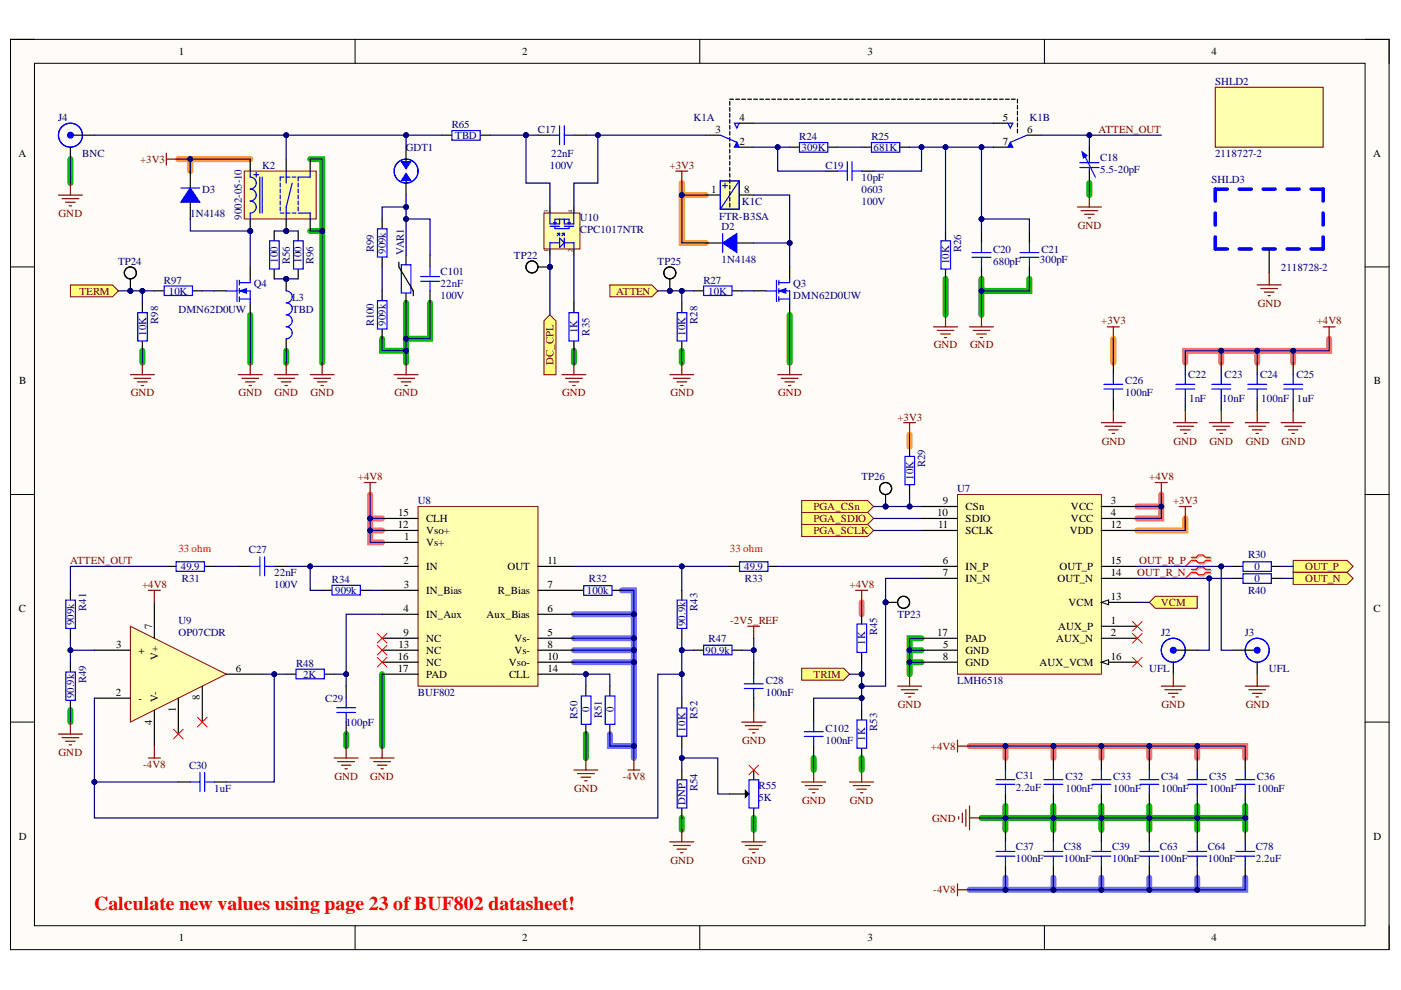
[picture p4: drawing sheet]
<svg xmlns="http://www.w3.org/2000/svg" width="297mm" height="210mm" viewBox="0 0 297 210" stroke-linecap="round" stroke-linejoin="round" font-family="sans-serif">
<defs><g id="words">
<text font-size="4.1" fill="#f00" x="20" y="192.9">Calculate new values using page 23 ofBUF802 datasheet!</text>
<g font-size="2.3">
<text x="37.9" y="11.7">1</text>
<text x="110.7" y="11.7">2</text>
<text x="183.9" y="11.7">3</text>
<text x="256.8" y="11.7">4</text>
<text x="151.7" y="28.1">3</text>
<text x="156.8" y="25.6">4</text>
<text x="212.6" y="25.6">5</text>
<text x="217.8" y="28.1">6</text>
<text x="3.9" y="33.3">A</text>
<text x="156.8" y="30.8">2</text>
<text x="212.6" y="30.8">7</text>
<text x="291.1" y="33.3">A</text>
<text x="150.8" y="40.9">1</text>
<text x="157.8" y="40.9">8</text>
<text x="4.1" y="81.5">B</text>
<text x="291.3" y="81.5">B</text>
<text x="199.9" y="106.9">9</text>
<text x="235.5" y="106.9">3</text>
<text x="84.3" y="112">12</text>
<text x="84.4" y="109.5">15</text>
<text x="90.4" y="113.3">Vso+</text>
<text x="90.4" y="110.7">CLH</text>
<text x="198.7" y="109.5">10</text>
<text x="198.9" y="112">11</text>
<text x="204.7" y="108.2">CSn</text>
<text x="204.7" y="110.7">SDIO</text>
<text x="204.7" y="113.3">SCLK</text>
<text x="226.8" y="113.3">VDD</text>
<text x="227.1" y="108.2">VCC</text>
<text x="227.1" y="110.7">VCC</text>
<text x="235.5" y="112">12</text>
<text x="235.5" y="109.5">4</text>
<text x="85.5" y="119.6">2</text>
<text x="85.7" y="114.5">1</text>
<text x="90.4" y="115.8">Vs+</text>
<text x="116.1" y="119.6">11</text>
<text x="199.9" y="119.6">6</text>
<text x="235.5" y="119.6">15</text>
<text x="85.6" y="124.7">3</text>
<text x="90.4" y="120.9">IN</text>
<text x="90.4" y="125.9">IN_Bias</text>
<text x="105.6" y="125.9">R_Bias</text>
<text x="107.6" y="120.9">OUT</text>
<text x="116.1" y="124.7">7</text>
<text x="199.9" y="122.1">7</text>
<text x="204.7" y="120.9">IN_P</text>
<text x="204.7" y="123.4">IN_N</text>
<text x="224.2" y="123.4">OUT_N</text>
<text x="224.6" y="120.9">OUT_P</text>
<text x="235.5" y="122.1">14</text>
<text x="4" y="129.7">C</text>
<text x="85.5" y="129.7">4</text>
<text x="90.4" y="131">IN_Aux</text>
<text x="103.1" y="131">Aux_Bias</text>
<text x="116.1" y="129.7">6</text>
<text x="226.6" y="128.5">VCM</text>
<text x="235.5" y="127.2">13</text>
<text x="291.2" y="129.7">C</text>
<text x="24.6" y="137.4">3</text>
<text x="32.2" y="133.3" transform="rotate(-90 32.2 133.3)">7</text>
<text x="84.5" y="137.4">13</text>
<text x="85.5" y="134.8">9</text>
<text x="90.4" y="136.1">NC</text>
<text x="109" y="136.1">Vs-</text>
<text x="116.1" y="134.8">5</text>
<text x="116.1" y="137.4">8</text>
<text x="198.7" y="134.8">17</text>
<text x="200" y="137.4">5</text>
<text x="204.7" y="136.1">PAD</text>
<text x="223.9" y="136.1">AUX_N</text>
<text x="224.4" y="133.6">AUX_P</text>
<text x="235.5" y="132.3">1</text>
<text x="235.5" y="134.8">2</text>
<text x="29.4" y="138.6">+</text>
<text x="33.5" y="140" transform="rotate(-90 33.5 140)">V+</text>
<text x="50" y="142.4">6</text>
<text x="84.3" y="139.9">16</text>
<text x="84.3" y="142.4">17</text>
<text x="90.4" y="138.6">NC</text>
<text x="90.4" y="141.2">NC</text>
<text x="90.4" y="143.7">PAD</text>
<text x="107.9" y="141.2">Vso-</text>
<text x="107.9" y="143.7">CLL</text>
<text x="109" y="138.6">Vs-</text>
<text x="116.1" y="139.9">10</text>
<text x="116.1" y="142.4">14</text>
<text x="199.9" y="139.9">8</text>
<text x="204.7" y="141.2">GND</text>
<text x="204.7" y="138.6">GND</text>
<text x="220.4" y="141.2">AUX_VCM</text>
<text x="235.5" y="139.9">16</text>
<text x="24.5" y="147.5">2</text>
<text x="29.4" y="148.9">-</text>
<text x="33.5" y="148.8" transform="rotate(-90 33.5 148.8)">V-</text>
<text x="42.4" y="148.5" transform="rotate(-90 42.4 148.5)">8</text>
<text x="32.2" y="153.7" transform="rotate(-90 32.2 153.7)">4</text>
<text x="37.3" y="150.9" transform="rotate(-90 37.3 150.9)">1</text>
<text x="4" y="178">D</text>
<text x="291.2" y="178">D</text>
<text x="37.9" y="199.6">1</text>
<text x="110.7" y="199.6">2</text>
<text x="183.9" y="199.6">3</text>
<text x="256.8" y="199.6">4</text>
</g>
<g font-size="2.3" fill="#000080">
<text x="257.6" y="18">SHLD2</text>
<text x="12.4" y="25.6">J4</text>
<text x="95.8" y="27.2">R65</text>
<text x="96.5" y="29.5">TBD</text>
<text x="114" y="28.1">C17</text>
<text x="147" y="25.6">K1A</text>
<text x="169.5" y="29.7">R24</text>
<text x="184.8" y="29.7">R25</text>
<text x="218.3" y="25.6">K1B</text>
<text x="17.4" y="33.3">BNC</text>
<text x="55.6" y="35.8">K2</text>
<text x="86" y="32">GDT1</text>
<text x="116.6" y="35.8">100V</text>
<text x="116.8" y="33.3">22nF</text>
<text x="170" y="32">309K</text>
<text x="175" y="35.8">C19</text>
<text x="185.2" y="32">681K</text>
<text x="233.2" y="34.1">C18</text>
<text x="257.6" y="33.3">2118727-2</text>
<text x="42.9" y="40.9">D3</text>
<text x="182.7" y="40.9">0603</text>
<text x="182.7" y="38.4">10pF</text>
<text x="233.2" y="36.6">5.5-20pF</text>
<text x="256.8" y="38.9">SHLD3</text>
<text x="40.4" y="46">1N4148</text>
<text x="51.3" y="46.7" transform="rotate(-90 51.3 46.7)">9002-05-10</text>
<text x="122.9" y="46.8">U10</text>
<text x="152.4" y="46.7">FTR-B3SA</text>
<text x="157.3" y="43.4">K1C</text>
<text x="182.7" y="43.4">100V</text>
<text x="79.3" y="53.4" transform="rotate(-90 79.3 53.4)">R99</text>
<text x="81.8" y="53.8" transform="rotate(-90 81.8 53.8)">909k</text>
<text x="122.9" y="49.4">CPC1017NTR</text>
<text x="153" y="48.8">D2</text>
<text x="203.8" y="53.4" transform="rotate(-90 203.8 53.4)">R26</text>
<text x="210.6" y="53.6">C20</text>
<text x="220.8" y="53.6">C21</text>
<text x="25" y="56.1">TP24</text>
<text x="58.9" y="55.7" transform="rotate(-90 58.9 55.7)">100</text>
<text x="61.4" y="56" transform="rotate(-90 61.4 56)">R56</text>
<text x="64" y="55.7" transform="rotate(-90 64 55.7)">100</text>
<text x="66.5" y="56" transform="rotate(-90 66.5 56)">R96</text>
<text x="85.6" y="54.1" transform="rotate(-90 85.6 54.1)">VAR1</text>
<text x="93.4" y="58.4">C101</text>
<text x="109" y="54.9">TP22</text>
<text x="139.4" y="56.1">TP25</text>
<text x="153" y="55.9">1N4148</text>
<text x="201.3" y="56" transform="rotate(-90 201.3 56)">10K</text>
<text x="210.6" y="56.1">680pF</text>
<text x="220.5" y="55.9">300pF</text>
<text x="271.6" y="57.4">2118728-2</text>
<text x="34.8" y="60.2">R97</text>
<text x="35.8" y="62.5">10K</text>
<text x="53.8" y="60.9">Q4</text>
<text x="61.9" y="63.7">L3</text>
<text x="93.4" y="63.5">100V</text>
<text x="93.4" y="60.9">22nF</text>
<text x="149.1" y="60.2">R27</text>
<text x="150.2" y="62.5">10K</text>
<text x="168.2" y="60.9">Q3</text>
<text x="168.2" y="63.5">DMN62D0UW</text>
<text x="31" y="71.3" transform="rotate(-90 31 71.3)">10K</text>
<text x="33.5" y="68.6" transform="rotate(-90 33.5 68.6)">R98</text>
<text x="37.8" y="66.3">DMN62D0UW</text>
<text x="61.9" y="66.3">TBD</text>
<text x="79.3" y="69.2" transform="rotate(-90 79.3 69.2)">R100</text>
<text x="81.8" y="69.1" transform="rotate(-90 81.8 69.1)">909k</text>
<text x="122.4" y="70.7" transform="rotate(-90 122.4 70.7)">1K</text>
<text x="125" y="71.2" transform="rotate(-90 125 71.2)">R35</text>
<text x="145.3" y="71.3" transform="rotate(-90 145.3 71.3)">10K</text>
<text x="147.9" y="68.6" transform="rotate(-90 147.9 68.6)">R28</text>
<text x="238.6" y="81.5">C26</text>
<text x="251.9" y="80.2">C22</text>
<text x="259.6" y="80.2">C23</text>
<text x="267.2" y="80.2">C24</text>
<text x="274.9" y="80.2">C25</text>
<text x="238.6" y="84">100nF</text>
<text x="252.1" y="85.3">1nF</text>
<text x="259.1" y="85.3">10nF</text>
<text x="267.4" y="85.3">100nF</text>
<text x="274.9" y="85.3">1uF</text>
<text x="182.7" y="101.9">TP26</text>
<text x="193.6" y="101.8" transform="rotate(-90 193.6 101.8)">10K</text>
<text x="196.2" y="99.1" transform="rotate(-90 196.2 99.1)">R29</text>
<text x="88.6" y="106.9">U8</text>
<text x="203" y="104.4">U7</text>
<text x="52.8" y="117.3">C27</text>
<text x="264.6" y="118.3">R30</text>
<text x="38.3" y="120.9">49.9</text>
<text x="38.6" y="123.4">R31</text>
<text x="58.1" y="124.7">100V</text>
<text x="58.1" y="122.1">22nF</text>
<text x="70.4" y="123.7">R34</text>
<text x="71.1" y="125.9">909k</text>
<text x="124.4" y="125.9">100k</text>
<text x="124.9" y="123.4">R32</text>
<text x="157.8" y="120.9">49.9</text>
<text x="157.9" y="123.4">R33</text>
<text x="264.6" y="125.9">R40</text>
<text x="266" y="120.9">0</text>
<text x="266" y="123.4">0</text>
<text x="18.3" y="129.5" transform="rotate(-90 18.3 129.5)">R41</text>
<text x="147.9" y="129.5" transform="rotate(-90 147.9 129.5)">R43</text>
<text x="190.3" y="131">TP23</text>
<text x="15.7" y="132.5" transform="rotate(-90 15.7 132.5)">909k</text>
<text x="37.8" y="132.3">U9</text>
<text x="37.8" y="134.8">OP07CDR</text>
<text x="145.3" y="132.8" transform="rotate(-90 145.3 132.8)">90.9k</text>
<text x="150.2" y="136.1">R47</text>
<text x="183.4" y="136.8" transform="rotate(-90 183.4 136.8)">1K</text>
<text x="186" y="134.7" transform="rotate(-90 186 134.7)">R45</text>
<text x="246.2" y="134.8">J2</text>
<text x="264" y="134.8">J3</text>
<text x="62.8" y="141.4">R48</text>
<text x="64.3" y="143.7">2K</text>
<text x="149.6" y="138.6">90.9k</text>
<text x="243.6" y="142.4">UFL</text>
<text x="269" y="142.4">UFL</text>
<text x="15.7" y="148.1" transform="rotate(-90 15.7 148.1)">90.9k</text>
<text x="18.3" y="144.8" transform="rotate(-90 18.3 144.8)">R49</text>
<text x="68.9" y="148.9">C29</text>
<text x="88.6" y="147.5">BUF802</text>
<text x="162.3" y="145">C28</text>
<text x="162.3" y="147.5">100nF</text>
<text x="203" y="145">LMH6518</text>
<text x="73.3" y="153.9">100pF</text>
<text x="122.4" y="152.4" transform="rotate(-90 122.4 152.4)">R50</text>
<text x="125" y="151.1" transform="rotate(-90 125 151.1)">0</text>
<text x="127.6" y="152.3" transform="rotate(-90 127.6 152.3)">R51</text>
<text x="130.1" y="151.1" transform="rotate(-90 130.1 151.1)">0</text>
<text x="145.3" y="155.1" transform="rotate(-90 145.3 155.1)">10K</text>
<text x="147.9" y="152.4" transform="rotate(-90 147.9 152.4)">R52</text>
<text x="175" y="155.2">C102</text>
<text x="186" y="154.9" transform="rotate(-90 186 154.9)">R53</text>
<text x="175" y="157.7">100nF</text>
<text x="183.4" y="157.1" transform="rotate(-90 183.4 157.1)">1K</text>
<text x="40.1" y="163.1">C30</text>
<text x="45.4" y="167.9">1uF</text>
<text x="147.9" y="167.7" transform="rotate(-90 147.9 167.7)">R54</text>
<text x="160.8" y="167.4">R55</text>
<text x="215.4" y="165.1">C31</text>
<text x="215.4" y="167.6">2.2uF</text>
<text x="225.9" y="165.3">C32</text>
<text x="225.9" y="167.9">100nF</text>
<text x="236" y="165.3">C33</text>
<text x="236" y="167.9">100nF</text>
<text x="246.2" y="165.3">C34</text>
<text x="246.2" y="167.9">100nF</text>
<text x="256.3" y="165.3">C35</text>
<text x="256.3" y="167.9">100nF</text>
<text x="266.5" y="165.3">C36</text>
<text x="266.5" y="167.9">100nF</text>
<text x="145.3" y="170.6" transform="rotate(-90 145.3 170.6)">DNP</text>
<text x="160.8" y="169.9">5K</text>
<text x="215.4" y="180.3">C37</text>
<text x="215.4" y="182.8">100nF</text>
<text x="225.5" y="180.3">C38</text>
<text x="225.5" y="182.8">100nF</text>
<text x="235.8" y="180.3">C39</text>
<text x="235.8" y="182.8">100nF</text>
<text x="245.9" y="180.3">C63</text>
<text x="245.9" y="182.8">100nF</text>
<text x="256.1" y="180.3">C64</text>
<text x="256.1" y="182.8">100nF</text>
<text x="266.2" y="180.3">C78</text>
<text x="266.2" y="182.8">2.2uF</text>
</g>
<g font-size="2.3" fill="#800000">
<text x="232.9" y="28.1">ATTEN_OUT</text>
<text x="29.7" y="34.6">+3V3</text>
<text x="142" y="35.8">+3V3</text>
<text x="12.4" y="46">GND</text>
<text x="228.5" y="48.5">GND</text>
<text x="16.8" y="62.5">TERM</text>
<text x="130.6" y="62.5">ATTEN</text>
<text x="266.7" y="65">GND</text>
<text x="233.5" y="68.8">+3V3</text>
<text x="279.2" y="68.8">+4V8</text>
<text x="117.3" y="77.3" transform="rotate(-90 117.3 77.3)">DC_CPL</text>
<text x="198" y="73.9">GND</text>
<text x="205.7" y="73.9">GND</text>
<text x="27.7" y="84">GND</text>
<text x="50.6" y="84">GND</text>
<text x="58.2" y="84">GND</text>
<text x="65.8" y="84">GND</text>
<text x="83.7" y="84">GND</text>
<text x="119.2" y="84">GND</text>
<text x="142.1" y="84">GND</text>
<text x="165" y="84">GND</text>
<text x="190.3" y="89.2">+3V3</text>
<text x="233.6" y="94.2">GND</text>
<text x="248.8" y="94.2">GND</text>
<text x="256.4" y="94.2">GND</text>
<text x="264.1" y="94.2">GND</text>
<text x="271.7" y="94.2">GND</text>
<text x="75.9" y="101.9">+4V8</text>
<text x="243.6" y="101.9">+4V8</text>
<text x="248.7" y="106.9">+3V3</text>
<text x="172.5" y="108.2">PGA_CSn</text>
<text x="172.5" y="113.3">PGA_SCLK</text>
<text x="172.5" y="110.7">PGA_SDIO</text>
<text x="14.9" y="119.6">ATTEN_OUT</text>
<text x="241.5" y="119.6">OUT_R_P</text>
<text x="30.1" y="124.7">+4V8</text>
<text x="180.1" y="124.7">+4V8</text>
<text x="241.1" y="122.1">OUT_R_N</text>
<text x="276.7" y="120.9">OUT_P</text>
<text x="276.7" y="123.4">OUT_N</text>
<text x="246.1" y="128.5">VCM</text>
<text x="154.8" y="132.3">-2V5_REF</text>
<text x="172.5" y="143.7">TRIM</text>
<text x="190.3" y="150.1">GND</text>
<text x="246.3" y="150.1">GND</text>
<text x="264.1" y="150.1">GND</text>
<text x="12.4" y="160.3">GND</text>
<text x="157.4" y="157.7">GND</text>
<text x="197.4" y="159">+4V8</text>
<text x="30.4" y="162.8">-4V8</text>
<text x="70.9" y="165.3">GND</text>
<text x="78.5" y="165.3">GND</text>
<text x="121.7" y="167.9">GND</text>
<text x="132.1" y="165.3">-4V8</text>
<text x="170" y="170.4">GND</text>
<text x="180.2" y="170.4">GND</text>
<text x="197.6" y="174.2">GND</text>
<text x="142.1" y="183.1">GND</text>
<text x="157.4" y="183.1">GND</text>
<text x="197.9" y="189.4">-4V8</text>
</g>
<g font-size="2.3" fill="#f00">
<text x="37.8" y="117.1">33 ohm</text>
<text x="154.7" y="117.1">33 ohm</text>
</g>
<g font-size="1.4">
<text x="116.3" y="45.1" transform="rotate(-90 116.3 45.1)">3</text>
<text x="121.4" y="45.1" transform="rotate(-90 121.4 45.1)">4</text>
<text x="116.3" y="53.3" transform="rotate(-90 116.3 53.3)">1</text>
<text x="121.4" y="53.4" transform="rotate(-90 121.4 53.4)">2</text>
</g>
</g></defs>
<path d="M2.2 8.3h292.3v193h-292.3z" fill-rule="evenodd" fill="#fffcf8"/>
<path d="M2.2 8.3h292.3v193h-292.3z" fill="none" stroke="#000" stroke-width=".21"/>
<path d="M7.3 13.4h282.1v182.9h-282.1z" fill-rule="evenodd" fill="#fffcf8"/>
<g fill="none" stroke="#000" stroke-width=".21">
<path d="M2.2 8.3h5.1M7.3 13.4h282.1v182.9h-282.1zM75.3 8.3v5.1M148.4 8.3v5.1M221.4 8.3v5.1M289.4 8.3h5.1v5.1M2.2 56.6h5.1M289.4 56.6h5.1M2.2 104.8h5.1M289.4 104.9h5.1M2.2 153.1h5.1M289.4 153.1h5.1"/>
<path d="M75.3 196.3v5M148.4 196.3v5M221.4 196.3v5M294.5 196.3v5"/>
</g>
<g fill="none" stroke="#00be00" stroke-width="1.3">
<path d="M14.9 33.7v5.1M65.8 33.7h2.5v15.3M231 38.8v2.6M65.8 49h2.5M68.3 49v27.9M200.5 59.1v7.7M208.1 59.1v7.7M218.3 59.1v2.6h-10.2M30.2 74.4v2.5M53.1 66.8v10.1M60.7 74.4v2.5M81 71.8v2.6h5.1"/>
<path d="M86.1 64.2v12.7M91.2 64.2v7.6h-5.1M121.7 74.4v2.5M144.6 74.4v2.5M167.4 66.8v10.1M192.8 137.9h2.6M195.4 135.3h-2.6v5.1h2.6M14.9 150.6v2.5M73.4 155.6v2.6M81 142.9v15.3M124.2 155.6v5.1M192.8 140.4v2.5"/>
<path d="M144.6 173.4v2.6M159.8 173.4v2.6M172.5 160.7v2.6M182.7 160.7v2.6M208.1 173.4h55.9M213.2 170.9v5.1M223.3 170.9v5.1M233.5 170.9v5.1M243.7 170.9v5.1M253.8 170.9v5.1M264 170.9v5.1"/>
</g>
<path d="M37.8 33.7h15.3M40.3 33.7v2.6M144.6 38.8v2.6h5M144.6 41.4v10.1h5M236.1 71.8v5.1M192.8 92.2v2.5M251.3 109.9v2.6h-10.2" fill="none" stroke="#f90" stroke-width="1.3"/>
<g fill="none" stroke="#ff6e6e" stroke-width="1.3">
<path d="M258.9 74.4h-7.6v2.5M266.6 74.4h-7.7v2.5M274.2 74.4v2.5M281.8 71.8v2.6h-15.2v2.5M78.5 104.8v10.2h2.5M78.5 112.5h2.5M78.5 109.9h2.5M241.1 107.4h5.1M246.2 104.9v5h-5.1M182.7 127.7v2.5M205.6 158.2h17.7v2.5M213.2 158.2v2.5"/>
<path d="M223.3 158.2h40.7v2.5M233.5 158.2v2.5M243.7 158.2v2.5M253.8 158.2v2.5"/>
</g>
<g fill="none" stroke="#6e6eff" stroke-width="1.3">
<path d="M121.7 130.2h12.7v5.1h-12.7M121.7 137.9h12.7M131.8 125.2h2.6v5M134.4 137.9v2.5h-12.7M134.4 135.3v2.6M129.3 155.6v2.6h5.1M134.4 140.4v20.3M213.2 186.1v2.6M223.3 186.1v2.6M233.5 186.1v2.6M243.7 186.1v2.6M253.8 186.1v2.6"/>
<path d="M264 186.1v2.6h-58.4"/>
</g>
<circle cx="116.6" cy="56.6" r=".51" fill="#000080"/>
<circle cx="116.6" cy="56.6" r=".51" fill="none" stroke="#000080" stroke-width=".21"/>
<path d="M114.1 56.6h2.5" fill="none" stroke="#000" stroke-width=".25"/>
<circle cx="116.6" cy="56.6" r=".51" fill="#000080"/>
<circle cx="116.6" cy="56.6" r=".51" fill="none" stroke="#000080" stroke-width=".21"/>
<g fill="none" stroke="#000" stroke-width=".25">
<path d="M269.1 52.8v5.1"/>
<circle cx="112.8" cy="56.6" r="1.27"/>
</g>
<path d="M257.7 45.2v2.5M257.7 50.2v2.6h2.5M260.2 40.1h-2.5v2.5M262.7 52.8h2.6M262.7 40.1h2.6M267.8 52.8h2.6M267.8 40.1h2.6M272.9 52.8h2.5M272.9 40.1h2.5M278 40.1h2.5v2.5M280.5 50.2v2.6h-2.5M280.5 45.2v2.5" fill="none" stroke="#00f" stroke-width=".76"/>
<path d="M269.1 57.9v2.5M266.6 60.4h5M267.3 61.2h3.6M268.1 61.9h2M268.8 62.7h.5" fill="none" stroke="#800000" stroke-width=".25"/>
<path d="M257.7 18.5h22.8v12.7h-22.8z" fill-rule="evenodd" fill="#ffffb0"/>
<path d="M257.7 18.5h22.8v12.7h-22.8z" fill="none" stroke="#800000" stroke-width=".21"/>
<path d="M152.7 38.4h4v6h-4z" fill-rule="evenodd" fill="#ffffb0"/>
<path d="M152.7 38.4h4v6h-4z" fill="none" stroke="#800000" stroke-width=".21"/>
<path d="M153.2 39.4h1M153.7 38.9v1M156.7 38.4l-4 6M156.7 38.4h-4v6M156.7 38.4v6h-4" fill="none" stroke="#00f" stroke-width=".25"/>
<path d="M149.6 41.4h3M149.6 51.5h3.8M156 51.5h3.8M156.8 41.4h3" fill="none" stroke="#000" stroke-width=".25"/>
<path d="M143.3 36.3h2.5M144.6 36.3v2.5" fill="none" stroke="#800000" stroke-width=".25"/>
<path d="M153.2 51.5l3-2v4z" fill="#00f"/>
<path d="M153.2 51.5l3-2v4zM153.2 49.5v4M164.6 59.4v4.5M165.1 59.9h2.3M165.1 59.4v1M162.3 61.7h2.3M165.1 61.7h2.3v2.5M165.1 63.4h2.3M165.1 61.2v1M165.1 62.9v1" fill="none" stroke="#00f" stroke-width=".25"/>
<path d="M167.4 56.6v2.5M159.8 61.7h2.5M167.4 64.2v2.6" fill="none" stroke="#000" stroke-width=".25"/>
<path d="M165.1 61.7l1.5-.5v1z" fill="#00f"/>
<path d="M165.1 61.7l1.5-.5v1z" fill="none" stroke="#00f" stroke-width=".21"/>
<path d="M167.4 59.1v.8M143.6 66.3h2v6h-2z" fill="none" stroke="#00f" stroke-width=".25"/>
<path d="M142 79.5h5.1M144.6 76.9v2.6M164.9 79.5h5.1M167.4 76.9v2.6M142.8 80.2h3.5M143.5 81h2.1M144.3 81.7h.5M165.6 80.2h3.6M166.4 81h2M167.2 81.7h.5" fill="none" stroke="#800000" stroke-width=".25"/>
<path d="M144.6 64.2v2M144.6 72.4v2" fill="none" stroke="#000" stroke-width=".25"/>
<path d="M129.3 60.4h8.9l1.3 1.3-1.3 1.2h-8.9z" fill-rule="evenodd" fill="#ffff80"/>
<path d="M129.3 60.4h8.9l1.3 1.3-1.3 1.2h-8.9z" fill="none" stroke="#800000" stroke-width=".21"/>
<g fill="none" stroke="#000" stroke-width=".25">
<path d="M149.6 28.7h3M154.7 21.5v.8M154.7 22.8v.8M154.7 24.1v.7M154.7 25.3v.8M154.7 26.6v.8M154.7 27.9v.8M154.7 29.1v.8M154.7 30.4v.8M154.7 31.7v.8M154.7 32.9v.8M154.7 34.2v.8"/>
<path d="M154.7 35.5v.8M154.7 36.8v.8M154.7 38v.8M154.7 39.3v.8M154.7 21h.8M156 21h.8M157.3 21h.8M158.5 21h.8M159.8 21h.8M161.1 21h.8M162.3 21h.8M163.6 21h.8"/>
<path d="M164.9 21h.8M166.2 21h.8M167.4 31.2h2M167.4 21h.8M168.7 21h.8M170 21h.8M171.2 21h.8M172.5 21h.8M173.8 21h.8M175.1 36.3h2.5M175.1 21h.8M175.6 31.2h2"/>
<path d="M176.3 21h.8M177.6 21h.8M178.9 21h.8M180.1 21h.8M181.4 21h.8M182.7 31.2h2M182.7 36.3h2.5M182.7 21h.8M184 21h.7M185.2 21h.8M186.5 21h.8M187.8 21h.8"/>
<path d="M189 21h.8M190.3 21h.8M190.8 31.2h2M191.6 21h.8M192.8 21h.8M194.1 21h.8M195.4 21h.8M196.7 21h.8M197.9 21h.8M199.2 21h.8M200.5 21h.8M201.7 21h.8"/>
<path d="M203 21h.8M204.3 21h.8M205.6 21h.7M206.8 21h.8M208.1 21h.8M209.4 21h.8M210.6 21h.8M211.9 21h.8M213.2 21h.8M214.4 21h.8M215.7 21v.8M215.7 22.3v.8"/>
<path d="M215.7 23.6v.8M215.7 24.9v.7M215.7 26.1v.8M215.7 27.4v.8M154.7 40.6v.8M154.7 41.8v.8M154.7 43.1v.8M200.5 49v2M200.5 57.1v2M208.1 49v2.5M208.1 56.6v2.5M218.3 49v2.5"/>
<path d="M218.3 56.6v2.5"/>
</g>
<g fill="none" stroke="#00f" stroke-width=".25">
<path d="M152.7 28.7l3.5 1.5M169.5 30.2h6v2.1h-6zM177.6 36.3h2M179.6 34.3v4M180.6 36.3h2.1M180.6 34.3v4M184.8 30.2h6v2.1h-6zM199.5 51.1h2v6h-2zM206.1 54.6h4M206.1 53.6h4M208.1 51.5v2.1M208.1 54.6v2"/>
<path d="M216.3 54.6h4M216.3 53.6h4M218.3 51.5v2.1M218.3 54.6v2"/>
</g>
<g fill="none" stroke="#800000" stroke-width=".25">
<path d="M228.4 43.9h5.1M229.2 44.7h3.5M230 45.4h2M230.7 46.2h.5M231 41.4v2.5M197.9 69.3h5.1M198.7 70.1h3.5M199.5 70.8h2M200.2 71.6h.5M200.5 66.8v2.5M205.6 69.3h5M206.3 70.1h3.6"/>
<path d="M207.1 70.8h2M207.8 71.6h.5M208.1 66.8v2.5"/>
</g>
<path d="M156.2 30.2l.5 1h-1z" fill="#00f"/>
<path d="M155.7 26.1h1l-.5 1.1zM156.2 30.2l.5 1h-1zM213.7 26.1h1l-.5 1.1zM217.7 28.7l-3.5 1.5" fill="none" stroke="#00f" stroke-width=".25"/>
<path d="M156.8 31.2h3M156.8 26.1h3M217.8 28.7h3" fill="none" stroke="#000" stroke-width=".25"/>
<path d="M214.2 30.2l.5 1h-1z" fill="#00f"/>
<path d="M116.6 28.7h2M118.6 26.7v4M119.6 28.7h2.1M119.6 26.7v4M214.2 30.2l.5 1h-1zM120.6 66.3h2.1v6h-2.1zM149.2 60.6h6v2.1h-6z" fill="none" stroke="#00f" stroke-width=".25"/>
<path d="M114.1 28.7h2.5M121.7 28.7h2.5M210.6 26.1h3M210.6 31.2h3M121.7 64.2v2M121.7 72.4v2M147.1 61.7h2M155.3 61.7h2" fill="none" stroke="#000" stroke-width=".25"/>
<path d="M83.6 79.5h5M86.1 76.9v2.6M119.1 79.5h5.1M121.7 76.9v2.6M84.3 80.2h3.6M85.1 81h2M85.8 81.7h.5M119.9 80.2h3.6M120.7 81h2M121.4 81.7h.5" fill="none" stroke="#800000" stroke-width=".25"/>
<path d="M115.3 68l1.3-1.2 1.3 1.2v11.5h-2.6z" fill-rule="evenodd" fill="#ffff80"/>
<path d="M115.3 68l1.3-1.2 1.3 1.2v11.5h-2.6z" fill="none" stroke="#800000" stroke-width=".21"/>
<circle cx="86.1" cy="36.3" r="2.54" fill="none" stroke="#00f" stroke-width=".25"/>
<path d="M85.1 34.3h2l-1 1.5z" fill="#00f"/>
<path d="M85.1 34.3h2l-1 1.5z" fill="none" stroke="#00f" stroke-width=".25"/>
<path d="M86.1 36.8l1 1.5h-2z" fill="#00f"/>
<path d="M86.1 36.8l1 1.5h-2z" fill="none" stroke="#00f" stroke-width=".25"/>
<path d="M86.1 31.2v2.9M86.1 38.4v3" fill="none" stroke="#000" stroke-width=".25"/>
<path d="M115.3 45.2h7.6v7.6h-7.6z" fill-rule="evenodd" fill="#ffffb0"/>
<path d="M115.3 45.2h7.6v7.6h-7.6z" fill="none" stroke="#800000" stroke-width=".21"/>
<path d="M231 31.2v2.5M231 36.3v2.5M116.6 43.9v1.3M116.6 52.8v1.3M121.7 43.9v1.3M121.7 52.8v1.3" fill="none" stroke="#000" stroke-width=".25"/>
<g fill="none" stroke="#00f" stroke-width=".25">
<path d="M230 33l2.2 4.6M116.6 45.2v2.3M116.6 48h2M117.4 47.2h.5l-.3 .3zM117.6 48v.5h3v-.5M117.6 47.5v-1h3v1M118.1 49.5h.5M118.6 49.5l-.5 .5M118.6 46.5v1h-2M118.6 49.5v.5M118.6 50.5l1 1-1 1zM118.6 51.5h-2v1.3"/>
<path d="M119.1 49.5h.5M119.6 49.5l-.5 .5M119.6 49.5v.5M119.6 50.5v2M119.6 48h2M119.6 51.5h2.1v1.3M120.4 47.2h.5l-.3 .3zM121.6 45v2.5h-2v-1"/>
</g>
<path d="M229.4 32.2l1.1 .8-.8 .5z" fill="#00f"/>
<g fill="none" stroke="#00f" stroke-width=".25">
<path d="M228.9 34.5h4.1M228.9 35.5h4.1M229.4 32.2l1.1 .8-.8 .5zM231 33.7v.8M231 35.5v.8"/>
<circle cx="14.9" cy="28.7" r="2.54"/>
</g>
<path d="M14.9 38.8v2.6M12.4 41.4h5.1M13.2 42.1h3.5M13.9 42.9h2M14.7 43.6h.5" fill="none" stroke="#800000" stroke-width=".25"/>
<path d="M14.9 28.7h5.1M14.9 31.2v2.5" fill="none" stroke="#000" stroke-width=".25"/>
<circle cx="14.9" cy="28.7" r=".64" fill="#00f"/>
<circle cx="14.9" cy="28.7" r=".64" fill="none" stroke="#00f" stroke-width=".21"/>
<circle cx="142" cy="61.7" r=".51" fill="#000080"/>
<circle cx="142" cy="61.7" r=".51" fill="none" stroke="#000080" stroke-width=".21"/>
<path d="M142 59.1v2.6" fill="none" stroke="#000" stroke-width=".25"/>
<circle cx="142" cy="61.7" r=".51" fill="#000080"/>
<circle cx="142" cy="61.7" r=".51" fill="none" stroke="#000080" stroke-width=".21"/>
<circle cx="142" cy="57.9" r="1.27" fill="none" stroke="#000" stroke-width=".25"/>
<path d="M12.4 155.6h5.1M13.2 156.4h3.5M13.9 157.2h2M14.7 157.9h.5M14.9 153.1v2.5" fill="none" stroke="#800000" stroke-width=".25"/>
<path d="M27.6 132.8l20.4 10.1-20.4 10.2z" fill="#ffffb0"/>
<path d="M27.6 132.8l20.4 10.1-20.4 10.2z" fill="none" stroke="#800000" stroke-width=".21"/>
<g fill="none" stroke="#000" stroke-width=".25">
<path d="M14.9 125.2v2M14.9 133.3v2M20 137.9h7.6M32.7 127.7v7.6M35.3 120.1h2M43.4 120.1h2M50.5 120.1h2.6M58.1 120.1h2.6M144.6 125.2v2M144.6 133.3v2M147.1 137.9h2M155.3 137.9h2"/>
<path d="M14.9 140.4v2M14.9 148.6v2M20 148h7.6M32.7 150.6v7.6M37.8 148v7.6M42.9 145.5v7.6M48 142.9h7.6M60.7 142.9h2M68.8 142.9h2M144.6 148v2M144.6 156.2v2M159.8 140.4v2.5"/>
<path d="M159.8 148v2.6M37.8 165.8h2.5M45.4 165.8h2.6M144.6 163.3v2M144.6 171.4v2M223.3 160.7v2.6M223.3 168.3v2.6M233.5 160.7v2.6M233.5 168.3v2.6M243.7 160.7v2.6M243.7 168.3v2.6M253.8 160.7v2.6"/>
<path d="M253.8 168.3v2.6M264 160.7v2.6M264 168.3v2.6"/>
</g>
<path d="M36.8 154.6l2 2.1M38.8 154.6l-2 2.1M41.9 152.1l2 2M43.9 152.1l-2 2" fill="none" stroke="#f00" stroke-width=".21"/>
<g fill="none" stroke="#00f" stroke-width=".25">
<path d="M37.3 119.1h6.1v2h-6.1zM55.1 118.1v4M56.1 118.1v4M14 127.2h2v6h-2zM53.1 120.1h2M56.1 120.1h2M143.6 127.2h2v6h-2zM149.2 136.8h6v2h-6zM14 142.5h2v6h-2zM62.8 141.9h6v2h-6zM143.6 150.1h2v6h-2zM157.8 145h4"/>
<path d="M157.8 146h4M159.8 142.9v2.1M159.8 146v2M40.3 165.8h2.1M42.4 163.8v4M43.4 165.8h2M43.4 163.8v4M143.6 165.3h2v6h-2zM221.3 165.3h4M221.3 166.3h4M223.3 163.3v2M223.3 166.3v2"/>
<path d="M231.5 165.3h4M231.5 166.3h4M233.5 163.3v2M233.5 166.3v2M241.7 165.3h4M241.7 166.3h4M243.7 163.3v2M243.7 166.3v2M251.8 165.3h4M251.8 166.3h4M253.8 163.3v2M253.8 166.3v2"/>
<path d="M262 165.3h4M262 166.3h4M264 163.3v2M264 166.3v2"/>
</g>
<g fill="none" stroke="#800000" stroke-width=".25">
<path d="M31.5 125.2h2.5M32.7 125.2v2.5M158.5 132.8h2.6M159.8 132.8v2.5M32.7 158.2v2.5M157.3 153.1h5M158 153.9h3.6M158.8 154.6h2M159.5 155.4h.6M159.8 150.6v2.5M31.5 160.7h2.5M142 178.5h5.1"/>
<path d="M142.8 179.3h3.5M144.6 176v2.5M143.5 180h2.1M144.3 180.8h.5"/>
</g>
<path d="M88.6 107.4h25.5v38.1h-25.5z" fill-rule="evenodd" fill="#ffffb0"/>
<path d="M88.6 107.4h25.5v38.1h-25.5z" fill="none" stroke="#800000" stroke-width=".21"/>
<g fill="none" stroke="#000" stroke-width=".25">
<path d="M81 115h7.6M81 112.5h7.6M81 109.9h7.6M68.3 125.2h2M76.5 125.2h2M81 120.1h7.6M81 125.2h7.6M81 130.2h7.6M81 135.3h7.6M81 137.9h7.6M114.1 120.1h7.6M114.1 125.2h9.6"/>
<path d="M114.1 130.2h7.6M114.1 135.3h7.6M114.1 137.9h7.6M129.8 125.2h2M154.7 120.1h2M162.9 120.1h2M73.4 145.5v2.5M73.4 153.1v2.5M81 140.4h7.6M81 142.9h7.6M114.1 140.4h7.6M114.1 142.9h7.6"/>
<path d="M124.2 145.5v2M124.2 153.6v2M154.7 168.3h4.1M159.8 163.3v2M159.8 171.4v2M213.2 160.7v2.6M213.2 168.3v2.6M213.2 176v2.5M223.3 176v2.5M233.5 176v2.5M243.7 176v2.5M253.8 176v2.5"/>
<path d="M264 176v2.5M213.2 183.6v2.5M223.3 183.6v2.5M233.5 183.6v2.5M243.7 183.6v2.5M253.8 183.6v2.5M264 183.6v2.5"/>
</g>
<path d="M80 134.3l2 2M80 136.8l2 2.1M80 139.4l2 2M82 134.3l-2 2M82 136.8l-2 2.1M82 139.4l-2 2M158.8 162.2l2 2.1M160.8 162.2l-2 2.1" fill="none" stroke="#f00" stroke-width=".21"/>
<g fill="none" stroke="#800000" stroke-width=".25">
<path d="M77.2 102.3h2.5M78.5 102.3v2.5M73.4 158.2v2.5M81 158.2v2.5M203 156.9v2.6M203 158.2h2.6M70.8 160.7h5.1M71.6 161.5h3.6M72.4 162.2h2M73.1 163h.5M78.5 160.7h5.1M79.2 161.5h3.6"/>
<path d="M80 162.2h2M80.8 163h.5M121.7 163.3h5.1M122.4 164h3.6M123.2 164.8h2M124 165.5h.5M124.2 160.7v2.6M133.1 163.3h2.6M134.4 160.7v2.6M157.3 178.5h5M158 179.3h3.6M159.8 176v2.5"/>
<path d="M158.8 180h2M159.6 180.8h.5M203 187.4v2.5M203 188.7h2.6"/>
</g>
<g fill="none" stroke="#00f" stroke-width=".25">
<path d="M156.8 119.1h6v2h-6zM70.4 124.1h6v2h-6zM123.8 124.2h6v2h-6zM71.4 151.1h4M71.4 150.1h4M73.4 148v2.1M73.4 151.1v2M123.2 147.6h2.1v6h-2.1zM158.8 165.3h2.1v6h-2.1zM211.2 166.3h4M211.2 165.3h4M213.2 163.3v2"/>
<path d="M213.2 166.3v2M213.2 178.5v2M223.3 178.5v2M233.5 178.5v2M243.7 178.5v2M253.8 178.5v2M264 178.5v2M211.2 181.5h4M211.2 180.5h4M213.2 181.5v2.1M221.3 181.5h4M221.3 180.5h4"/>
<path d="M223.3 181.5v2.1M231.5 181.5h4M231.5 180.5h4M233.5 181.5v2.1M241.7 181.5h4M241.7 180.5h4M243.7 181.5v2.1M251.8 181.5h4M251.8 180.5h4M253.8 181.5v2.1M262 181.5h4M262 180.5h4"/>
<path d="M264 181.5v2.1"/>
</g>
<path d="M158 167.6l.8 .7-.8 .8z" fill="#000"/>
<path d="M158 167.6l.8 .7-.8 .8z" fill="none" stroke="#000" stroke-width=".21"/>
<path d="M203 104.9h30.5v38h-30.5z" fill-rule="evenodd" fill="#ffffb0"/>
<path d="M203 104.9h30.5v38h-30.5z" fill="none" stroke="#800000" stroke-width=".21"/>
<path d="M195.4 107.4h7.6M195.4 109.9h7.6M195.4 112.5h7.6M233.5 112.5h7.6M233.5 127.7h7.6" fill="none" stroke="#000" stroke-width=".25"/>
<path d="M233.5 127.7l1.5-.5v1z" fill="#f8fcff"/>
<path d="M233.5 127.7l1.5-.5v1z" fill="none" stroke="#000" stroke-width=".21"/>
<path d="M233.5 122.6h7.6M233.5 120.1h7.6M233.5 132.8h7.6M233.5 135.3h7.6M233.5 140.4h7.6" fill="none" stroke="#000" stroke-width=".25"/>
<path d="M233.5 140.4l1.5-.5v1z" fill="#f8fcff"/>
<path d="M233.5 140.4l1.5-.5v1z" fill="none" stroke="#000" stroke-width=".21"/>
<path d="M233.5 107.4h7.6M233.5 109.9h7.6M195.4 137.9h7.6M195.4 135.3h7.6M195.4 120.1h7.6M195.4 122.6h7.6M195.4 140.4h7.6" fill="none" stroke="#000" stroke-width=".25"/>
<path d="M170 106.1h14l1.2 1.3-1.2 1.3h-14z" fill-rule="evenodd" fill="#ffff80"/>
<path d="M170 106.1h14l1.2 1.3-1.2 1.3h-14z" fill="none" stroke="#800000" stroke-width=".21"/>
<path d="M192.8 94.7v2M192.8 102.8v2.1" fill="none" stroke="#000" stroke-width=".25"/>
<path d="M191.9 96.8h2v6h-2z" fill="none" stroke="#00f" stroke-width=".25"/>
<path d="M191.6 89.6h2.5M192.8 89.6v2.6" fill="none" stroke="#800000" stroke-width=".25"/>
<path d="M170 111.2h14l1.2 1.3-1.2 1.2h-14z" fill-rule="evenodd" fill="#ffff80"/>
<path d="M170 111.2h14l1.2 1.3-1.2 1.2h-14z" fill="none" stroke="#800000" stroke-width=".21"/>
<path d="M170 108.7h14l1.2 1.2-1.2 1.3h-14z" fill-rule="evenodd" fill="#ffff80"/>
<path d="M170 108.7h14l1.2 1.2-1.2 1.3h-14z" fill="none" stroke="#800000" stroke-width=".21"/>
<path d="M190.3 145.5h5.1M191.1 146.2h3.5M191.8 147h2.1M192.6 147.8h.5M192.8 142.9v2.6" fill="none" stroke="#800000" stroke-width=".25"/>
<path d="M244.9 126.4h8.9v2.6h-8.9l-1.2-1.3z" fill-rule="evenodd" fill="#ffff80"/>
<path d="M244.9 126.4h8.9v2.6h-8.9l-1.2-1.3z" fill="none" stroke="#800000" stroke-width=".21"/>
<path d="M250 107.4h2.6M251.3 107.4v2.5M180.1 165.8h5.1M180.9 166.6h3.6M181.7 167.3h2M182.4 168.1h.5M182.7 163.3v2.5" fill="none" stroke="#800000" stroke-width=".25"/>
<path d="M182.7 130.2v2M182.7 138.4v2M182.7 150.6v2M182.7 158.7v2" fill="none" stroke="#000" stroke-width=".25"/>
<path d="M181.7 132.3h2v6h-2zM181.7 152.6h2v6h-2z" fill="none" stroke="#00f" stroke-width=".25"/>
<path d="M240.1 131.8l2.1 2M240.1 134.3l2.1 2M240.1 139.4l2.1 2M242.2 131.8l-2.1 2M242.2 134.3l-2.1 2M242.2 139.4l-2.1 2" fill="none" stroke="#f00" stroke-width=".21"/>
<path d="M170 141.7h8.9l1.2 1.2-1.2 1.3h-8.9z" fill-rule="evenodd" fill="#ffff80"/>
<path d="M170 141.7h8.9l1.2 1.2-1.2 1.3h-8.9z" fill="none" stroke="#800000" stroke-width=".21"/>
<path d="M181.4 125.2h2.6M182.7 125.2v2.5" fill="none" stroke="#800000" stroke-width=".25"/>
<circle cx="187.8" cy="127.7" r=".51" fill="#000080"/>
<circle cx="187.8" cy="127.7" r=".51" fill="none" stroke="#000080" stroke-width=".21"/>
<path d="M187.8 127.7h2.5" fill="none" stroke="#000" stroke-width=".25"/>
<circle cx="187.8" cy="127.7" r=".51" fill="#000080"/>
<circle cx="187.8" cy="127.7" r=".51" fill="none" stroke="#000080" stroke-width=".21"/>
<circle cx="191.6" cy="127.7" r="1.27" fill="none" stroke="#000" stroke-width=".25"/>
<path d="M274.2 118.8h11.4l1.3 1.3-1.3 1.3h-11.4z" fill-rule="evenodd" fill="#ffff80"/>
<path d="M274.2 118.8h11.4l1.3 1.3-1.3 1.3h-11.4z" fill="none" stroke="#800000" stroke-width=".21"/>
<path d="M274.2 121.4h11.4l1.3 1.2-1.3 1.3h-11.4z" fill-rule="evenodd" fill="#ffff80"/>
<path d="M274.2 121.4h11.4l1.3 1.2-1.3 1.3h-11.4z" fill="none" stroke="#800000" stroke-width=".21"/>
<path d="M248.8 137.9h5M261.5 120.1h2M261.5 122.6h2M269.6 120.1h2M269.6 122.6h2M248.8 140.4v2.5" fill="none" stroke="#000" stroke-width=".25"/>
<g fill="none" stroke="#00f" stroke-width=".25">
<path d="M263.5 119.1h6.1v2h-6.1zM263.5 121.7h6.1v2h-6.1z"/>
<circle cx="248.8" cy="137.9" r="2.54"/>
</g>
<circle cx="248.8" cy="137.9" r=".64" fill="#00f"/>
<circle cx="248.8" cy="137.9" r=".64" fill="none" stroke="#00f" stroke-width=".21"/>
<path d="M246.2 145.5h5.1M247 146.2h3.5M247.7 147h2.1M248.5 147.8h.5M248.8 142.9v2.6" fill="none" stroke="#800000" stroke-width=".25"/>
<circle cx="266.6" cy="137.9" r="2.54" fill="none" stroke="#00f" stroke-width=".25"/>
<path d="M261.5 137.9h5.1M266.6 140.4v2.5" fill="none" stroke="#000" stroke-width=".25"/>
<circle cx="266.6" cy="137.9" r=".63" fill="#00f"/>
<circle cx="266.6" cy="137.9" r=".63" fill="none" stroke="#00f" stroke-width=".21"/>
<path d="M264 145.5h5.1M264.8 146.2h3.5M265.5 147h2.1M266.3 147.8h.5M266.6 142.9v2.6" fill="none" stroke="#800000" stroke-width=".25"/>
<path d="M252.8 118.4h1l.5-.5h1.1l.5 .5h1M252.8 119.1h1l.5 .5h1.1l.5-.5h1" fill="none" stroke="#d0a19e" stroke-width=".25"/>
<path d="M252.8 119.1l-1.5 1" fill="none" stroke="#d0a19e" stroke-width=".21"/>
<path d="M252.6 118.2h1l.5-.5h1l.5 .5h1M252.6 118.8h1l.5 .5h1l.5-.5h1" fill="none" stroke="#f00" stroke-width=".25"/>
<path d="M252.6 118.8l-1.3 1.3" fill="none" stroke="#f00" stroke-width=".21"/>
<circle cx="187.8" cy="107.4" r=".51" fill="#000080"/>
<circle cx="187.8" cy="107.4" r=".51" fill="none" stroke="#000080" stroke-width=".21"/>
<path d="M187.8 104.9v2.5" fill="none" stroke="#000" stroke-width=".25"/>
<circle cx="187.8" cy="107.4" r=".51" fill="#000080"/>
<circle cx="187.8" cy="107.4" r=".51" fill="none" stroke="#000080" stroke-width=".21"/>
<g fill="none" stroke="#000" stroke-width=".25">
<path d="M84.6 55.6v1l3 5.1v1M86.1 54.1v2M86.1 62.2v2M236.1 76.9v2.6M251.3 76.9v2.6M258.9 76.9v2.6M266.6 76.9v2.6M274.2 76.9v2.6M236.1 84.5v2.6M251.3 84.5v2.6M258.9 84.5v2.6M266.6 84.5v2.6"/>
<path d="M274.2 84.5v2.6M129.3 145.5v2M129.3 153.6v2"/>
<circle cx="187.8" cy="103.6" r="1.27"/>
</g>
<g fill="none" stroke="#00f" stroke-width=".25">
<path d="M85.1 56.1h2v6h-2zM236.1 79.5v2M251.3 79.5v2M258.9 79.5v2M266.6 79.5v2M274.2 79.5v2M234.1 82.5h4M234.1 81.5h4M236.1 82.5v2M249.3 82.5h4M249.3 81.5h4M251.3 82.5v2"/>
<path d="M256.9 82.5h4M256.9 81.5h4M258.9 82.5v2M264.6 82.5h4M264.6 81.5h4M266.6 82.5v2M272.2 82.5h4M272.2 81.5h4M274.2 82.5v2M128.3 147.6h2.1v6h-2.1z"/>
</g>
<g fill="none" stroke="#800000" stroke-width=".25">
<path d="M234.8 69.3h2.5M236.1 69.3v2.5M280.5 69.3h2.6M281.8 69.3v2.5M233.5 89.6h5.1M234.3 90.4h3.5M235 91.1h2.1M235.8 91.9h.5M236.1 87.1v2.5M248.8 89.6h5M249.5 90.4h3.6M250.3 91.1h2"/>
<path d="M251 91.9h.6M251.3 87.1v2.5M256.4 89.6h5.1M257.2 90.4h3.5M257.9 91.1h2M258.7 91.9h.5M258.9 87.1v2.5M264 89.6h5.1M264.8 90.4h3.5M265.5 91.1h2.1M266.3 91.9h.5M266.6 87.1v2.5"/>
<path d="M271.6 89.6h5.1M272.4 90.4h3.6M273.2 91.1h2M273.9 91.9h.5M274.2 87.1v2.5M244.9 102.3h2.6M246.2 102.3v2.6M203.3 173.2v.5M204 172.4v2M204.8 171.6v3.6M205.6 170.9v5.1M205.6 173.4h2.5"/>
</g>
<path d="M252.8 121h1l.5-.5h1.1l.5 .5h1M252.8 121.6h1l.5 .5h1.1l.5-.5h1" fill="none" stroke="#d0a19e" stroke-width=".25"/>
<path d="M252.8 121.6l-1.5 1" fill="none" stroke="#d0a19e" stroke-width=".21"/>
<path d="M252.6 120.7h1l.5-.5h1l.5 .5h1M252.6 121.4h1l.5 .5h1l.5-.5h1" fill="none" stroke="#f00" stroke-width=".25"/>
<path d="M252.6 121.4l-1.3 1.2" fill="none" stroke="#f00" stroke-width=".21"/>
<path d="M14.9 60.4h8.9l1.3 1.3-1.3 1.2h-8.9z" fill-rule="evenodd" fill="#ffff80"/>
<path d="M14.9 60.4h8.9l1.3 1.3-1.3 1.2h-8.9z" fill="none" stroke="#800000" stroke-width=".21"/>
<path d="M40.3 36.3v3.8M40.3 42.6v3.8" fill="none" stroke="#000" stroke-width=".25"/>
<path d="M40.3 39.9l2 3h-4z" fill="#00f"/>
<path d="M38.3 39.9h4M40.3 39.9l2 3h-4zM50.3 59.4v4.5M50.8 59.9h2.3M50.8 59.4v1M48 61.7h2.3M50.8 61.7h2.3v2.5M50.8 63.4h2.3M50.8 61.2v1M50.8 62.9v1" fill="none" stroke="#00f" stroke-width=".25"/>
<path d="M53.1 56.6v2.5M45.4 61.7h2.6M53.1 64.2v2.6" fill="none" stroke="#000" stroke-width=".25"/>
<path d="M50.8 61.7l1.5-.5v1z" fill="#00f"/>
<path d="M50.8 61.7l1.5-.5v1z" fill="none" stroke="#00f" stroke-width=".21"/>
<path d="M53.1 59.1v.8M29.2 66.3h2v6h-2zM34.8 60.6h6v2.1h-6z" fill="none" stroke="#00f" stroke-width=".25"/>
<path d="M27.6 79.5h5.1M30.2 76.9v2.6M50.5 79.5h5.1M53.1 76.9v2.6M28.4 80.2h3.6M29.2 81h2M29.9 81.7h.5M51.3 80.2h3.5M52 81h2.1M52.8 81.7h.5" fill="none" stroke="#800000" stroke-width=".25"/>
<path d="M30.2 64.2v2M30.2 72.4v2M32.7 61.7h2M40.9 61.7h2" fill="none" stroke="#000" stroke-width=".25"/>
<circle cx="27.6" cy="61.7" r=".51" fill="#000080"/>
<circle cx="27.6" cy="61.7" r=".51" fill="none" stroke="#000080" stroke-width=".21"/>
<path d="M27.6 59.1v2.6" fill="none" stroke="#000" stroke-width=".25"/>
<circle cx="27.6" cy="61.7" r=".51" fill="#000080"/>
<circle cx="27.6" cy="61.7" r=".51" fill="none" stroke="#000080" stroke-width=".21"/>
<circle cx="27.6" cy="57.9" r="1.27" fill="none" stroke="#000" stroke-width=".25"/>
<path d="M58.1 79.5h5.1M60.7 76.9v2.6M58.9 80.2h3.6M59.7 81h2M60.4 81.7h.5" fill="none" stroke="#800000" stroke-width=".25"/>
<circle cx="60.7" cy="59.1" r=".51" fill="#000080"/>
<circle cx="60.7" cy="59.1" r=".51" fill="none" stroke="#000080" stroke-width=".21"/>
<path d="M60.7 59.1v2.6" fill="none" stroke="#000" stroke-width=".25"/>
<circle cx="60.7" cy="59.1" r=".51" fill="#000080"/>
<circle cx="60.7" cy="59.1" r=".51" fill="none" stroke="#000080" stroke-width=".21"/>
<path d="M58.1 49v2M58.1 57.1v2M63.2 49v2M63.2 57.1v2M60.7 71.8v2.6" fill="none" stroke="#000" stroke-width=".25"/>
<path d="M57.2 51.1h2v6h-2zM62.2 51.1h2.1v6h-2.1zM60.7 61.7a1.27 1.27 0 0 1 1.3 1.2 1.27 1.27 0 0 1-1.3 1.3 1.27 1.27 0 0 1 1.3 1.3 1.27 1.27 0 0 1-1.3 1.3 1.27 1.27 0 0 1 1.3 1.2 1.27 1.27 0 0 1-1.3 1.3 1.27 1.27 0 0 1 1.3 1.3 1.27 1.27 0 0 1-1.3 1.2" fill="none" stroke="#00f" stroke-width=".25"/>
<path d="M35.3 32.5v2.5M35.3 33.7h2.5" fill="none" stroke="#800000" stroke-width=".25"/>
<circle cx="53.1" cy="49" r=".51" fill="#000080"/>
<circle cx="53.1" cy="49" r=".51" fill="none" stroke="#000080" stroke-width=".21"/>
<circle cx="60.7" cy="49" r=".51" fill="#000080"/>
<circle cx="60.7" cy="49" r=".51" fill="none" stroke="#000080" stroke-width=".21"/>
<path d="M51.8 36.3h15.2v10.1h-15.2z" fill-rule="evenodd" fill="#ffffb0"/>
<path d="M51.8 36.3h15.2v10.1h-15.2z" fill="none" stroke="#800000" stroke-width=".21"/>
<path d="M53.1 33.7v2.6M53.1 46.4v2.6" fill="none" stroke="#000" stroke-width=".25"/>
<circle cx="53.1" cy="49" r=".51" fill="#000080"/>
<circle cx="53.1" cy="49" r=".51" fill="none" stroke="#000080" stroke-width=".21"/>
<path d="M53.1 36.3v1.3a1.27 1.27 0 0 1 1.2 1.2 1.27 1.27 0 0 1-1.2 1.3 1.27 1.27 0 0 1 1.2 1.3 1.27 1.27 0 0 1-1.2 1.2 1.27 1.27 0 0 1 1.2 1.3 1.27 1.27 0 0 1-1.2 1.3v1.2M60.7 36.3v2.5M62 38.8l-1.3 5.1v2.5" fill="none" stroke="#00f" stroke-width=".25"/>
<path d="M60.7 33.7v2.6M60.7 46.4v2.6" fill="none" stroke="#000" stroke-width=".25"/>
<circle cx="60.7" cy="49" r=".51" fill="#000080"/>
<circle cx="60.7" cy="49" r=".51" fill="none" stroke="#000080" stroke-width=".21"/>
<g fill="none" stroke="#00f" stroke-width=".25">
<path d="M53.8 37h1M54.3 36.5v1.1M55.1 37.6v7.6M55.6 37.6v7.6M59.4 38.8v.8M60.2 37.6h-.8v.7M60.7 37.6h.8M62 37.6h.7M63.2 38.8v.8M65.8 36.3v1.3h-2.6v.7M95.8 27.7h6v2h-6zM59.4 40.1v.8"/>
<path d="M59.4 41.4v.8M59.4 42.6v.8M59.4 43.9v.8M59.4 45.2h.8M60.7 45.2h.8M62 45.2h.7M63.2 40.1v.8M63.2 41.4v.8M63.2 42.6v.8M63.2 43.9v.8M63.2 45.2h2.6v1.2M80 48.5h2.1v6h-2.1z"/>
<path d="M89.2 58.6h4M89.2 59.6h4M91.2 56.6v2M91.2 59.6v2.1M80 63.8h2.1v6h-2.1zM170.5 155.1h4M170.5 156.1h4M172.5 153.1v2M172.5 156.1v2.1"/>
</g>
<path d="M65.8 33.7v2.6M93.7 28.7h2M101.9 28.7h2M65.8 46.4v2.6M81 46.4v2M81 54.6v2M91.2 54.1v2.5M81 61.7v2M81 69.8v2M91.2 61.7v2.5M172.5 150.6v2.5M172.5 158.2v2.5" fill="none" stroke="#000" stroke-width=".25"/>
<path d="M65.8 79.5h5M68.3 76.9v2.6M66.5 80.2h3.6M67.3 81h2M68 81.7h.6M170 165.8h5.1M170.7 166.6h3.6M171.5 167.3h2M172.3 168.1h.5M172.5 163.3v2.5" fill="none" stroke="#800000" stroke-width=".25"/>
<path d="M126.8 28.7h22.8M231 38.8v2.6" fill="none" stroke="#000080" stroke-width=".25"/>
<circle cx="126.8" cy="28.7" r=".51" fill="#000080"/>
<circle cx="126.8" cy="28.7" r=".51" fill="none" stroke="#000080" stroke-width=".21"/>
<path d="M139.5 61.7h5.1" fill="none" stroke="#000080" stroke-width=".25"/>
<circle cx="144.6" cy="61.7" r=".51" fill="#000080"/>
<circle cx="144.6" cy="61.7" r=".51" fill="none" stroke="#000080" stroke-width=".21"/>
<circle cx="142" cy="61.7" r=".51" fill="#000080"/>
<circle cx="142" cy="61.7" r=".51" fill="none" stroke="#000080" stroke-width=".21"/>
<path d="M147.1 61.7h-2.5v2.5" fill="none" stroke="#000080" stroke-width=".25"/>
<circle cx="144.6" cy="61.7" r=".51" fill="#000080"/>
<circle cx="144.6" cy="61.7" r=".51" fill="none" stroke="#000080" stroke-width=".21"/>
<path d="M144.6 41.4v10.1h5" fill="none" stroke="#000080" stroke-width=".25"/>
<circle cx="144.6" cy="41.4" r=".51" fill="#000080"/>
<circle cx="144.6" cy="41.4" r=".51" fill="none" stroke="#000080" stroke-width=".21"/>
<path d="M144.6 38.8v2.6h5" fill="none" stroke="#000080" stroke-width=".25"/>
<circle cx="144.6" cy="41.4" r=".51" fill="#000080"/>
<circle cx="144.6" cy="41.4" r=".51" fill="none" stroke="#000080" stroke-width=".21"/>
<path d="M159.8 51.5h7.6M157.3 61.7h2.5" fill="none" stroke="#000080" stroke-width=".25"/>
<circle cx="167.4" cy="51.5" r=".51" fill="#000080"/>
<circle cx="167.4" cy="51.5" r=".51" fill="none" stroke="#000080" stroke-width=".21"/>
<path d="M159.8 26.1h50.8M164.9 31.2v5.1h10.2" fill="none" stroke="#000080" stroke-width=".25"/>
<circle cx="164.9" cy="31.2" r=".51" fill="#000080"/>
<circle cx="164.9" cy="31.2" r=".51" fill="none" stroke="#000080" stroke-width=".21"/>
<path d="M195.4 31.2v5.1h-10.2" fill="none" stroke="#000080" stroke-width=".25"/>
<circle cx="195.4" cy="31.2" r=".51" fill="#000080"/>
<circle cx="195.4" cy="31.2" r=".51" fill="none" stroke="#000080" stroke-width=".21"/>
<path d="M218.3 59.1v2.6h-10.2" fill="none" stroke="#000080" stroke-width=".25"/>
<circle cx="208.1" cy="61.7" r=".51" fill="#000080"/>
<circle cx="208.1" cy="61.7" r=".51" fill="none" stroke="#000080" stroke-width=".21"/>
<path d="M208.1 46.4h10.2v2.6" fill="none" stroke="#000080" stroke-width=".25"/>
<circle cx="208.1" cy="46.4" r=".51" fill="#000080"/>
<circle cx="208.1" cy="46.4" r=".51" fill="none" stroke="#000080" stroke-width=".21"/>
<path d="M86.1 28.7v2.5" fill="none" stroke="#000080" stroke-width=".25"/>
<circle cx="86.1" cy="28.7" r=".51" fill="#000080"/>
<circle cx="86.1" cy="28.7" r=".51" fill="none" stroke="#000080" stroke-width=".21"/>
<path d="M231 28.7v2.5M200.5 59.1v7.7M121.7 74.4v2.5M144.6 74.4v2.5M167.4 66.8v10.1" fill="none" stroke="#000080" stroke-width=".25"/>
<circle cx="231" cy="28.7" r=".51" fill="#000080"/>
<circle cx="231" cy="28.7" r=".51" fill="none" stroke="#000080" stroke-width=".21"/>
<path d="M200.5 31.2v17.8M121.7 54.1v10.1" fill="none" stroke="#000080" stroke-width=".25"/>
<circle cx="200.5" cy="31.2" r=".51" fill="#000080"/>
<circle cx="200.5" cy="31.2" r=".51" fill="none" stroke="#000080" stroke-width=".21"/>
<path d="M14.9 33.7v5.1M177.6 31.2h5.1M159.8 137.9v2.5" fill="none" stroke="#000080" stroke-width=".25"/>
<circle cx="159.8" cy="137.9" r=".51" fill="#000080"/>
<circle cx="159.8" cy="137.9" r=".51" fill="none" stroke="#000080" stroke-width=".21"/>
<path d="M20 137.9h-5.1v2.5" fill="none" stroke="#000080" stroke-width=".25"/>
<circle cx="14.9" cy="137.9" r=".51" fill="#000080"/>
<circle cx="14.9" cy="137.9" r=".51" fill="none" stroke="#000080" stroke-width=".21"/>
<path d="M55.6 142.9h2.5v22.9h-10.1" fill="none" stroke="#000080" stroke-width=".25"/>
<circle cx="58.1" cy="142.9" r=".51" fill="#000080"/>
<circle cx="58.1" cy="142.9" r=".51" fill="none" stroke="#000080" stroke-width=".21"/>
<path d="M144.6 137.9h2.5" fill="none" stroke="#000080" stroke-width=".25"/>
<circle cx="144.6" cy="137.9" r=".51" fill="#000080"/>
<circle cx="144.6" cy="137.9" r=".51" fill="none" stroke="#000080" stroke-width=".21"/>
<path d="M213.2 158.2v2.5" fill="none" stroke="#000080" stroke-width=".25"/>
<circle cx="213.2" cy="158.2" r=".51" fill="#000080"/>
<circle cx="213.2" cy="158.2" r=".51" fill="none" stroke="#000080" stroke-width=".21"/>
<path d="M233.5 158.2v2.5" fill="none" stroke="#000080" stroke-width=".25"/>
<circle cx="233.5" cy="158.2" r=".51" fill="#000080"/>
<circle cx="233.5" cy="158.2" r=".51" fill="none" stroke="#000080" stroke-width=".21"/>
<path d="M243.7 158.2v2.5" fill="none" stroke="#000080" stroke-width=".25"/>
<circle cx="243.7" cy="158.2" r=".51" fill="#000080"/>
<circle cx="243.7" cy="158.2" r=".51" fill="none" stroke="#000080" stroke-width=".21"/>
<path d="M14.9 135.3v2.6M14.9 150.6v2.5" fill="none" stroke="#000080" stroke-width=".25"/>
<circle cx="14.9" cy="137.9" r=".51" fill="#000080"/>
<circle cx="14.9" cy="137.9" r=".51" fill="none" stroke="#000080" stroke-width=".21"/>
<path d="M253.8 158.2v2.5" fill="none" stroke="#000080" stroke-width=".25"/>
<circle cx="253.8" cy="158.2" r=".51" fill="#000080"/>
<circle cx="253.8" cy="158.2" r=".51" fill="none" stroke="#000080" stroke-width=".21"/>
<path d="M45.4 120.1h5.1M58.1 142.9h2.6M144.6 173.4v2.6" fill="none" stroke="#000080" stroke-width=".25"/>
<circle cx="58.1" cy="142.9" r=".51" fill="#000080"/>
<circle cx="58.1" cy="142.9" r=".51" fill="none" stroke="#000080" stroke-width=".21"/>
<path d="M35.3 120.1h-20.4v5.1M81 142.9v15.3M124.2 142.9v2.6" fill="none" stroke="#000080" stroke-width=".25"/>
<circle cx="124.2" cy="142.9" r=".51" fill="#000080"/>
<circle cx="124.2" cy="142.9" r=".51" fill="none" stroke="#000080" stroke-width=".21"/>
<path d="M131.8 125.2h2.6v5M124.2 155.6v5.1" fill="none" stroke="#000080" stroke-width=".25"/>
<circle cx="134.4" cy="130.2" r=".51" fill="#000080"/>
<circle cx="134.4" cy="130.2" r=".51" fill="none" stroke="#000080" stroke-width=".21"/>
<path d="M78.5 112.5h2.5" fill="none" stroke="#000080" stroke-width=".25"/>
<circle cx="78.5" cy="112.5" r=".51" fill="#000080"/>
<circle cx="78.5" cy="112.5" r=".51" fill="none" stroke="#000080" stroke-width=".21"/>
<path d="M78.5 109.9h2.5" fill="none" stroke="#000080" stroke-width=".25"/>
<circle cx="78.5" cy="109.9" r=".51" fill="#000080"/>
<circle cx="78.5" cy="109.9" r=".51" fill="none" stroke="#000080" stroke-width=".21"/>
<path d="M73.4 142.9v2.6" fill="none" stroke="#000080" stroke-width=".25"/>
<circle cx="73.4" cy="142.9" r=".51" fill="#000080"/>
<circle cx="73.4" cy="142.9" r=".51" fill="none" stroke="#000080" stroke-width=".21"/>
<path d="M73.4 155.6v2.6M144.6 160.7h7.6v7.6h2.5M159.8 173.4v2.6" fill="none" stroke="#000080" stroke-width=".25"/>
<circle cx="144.6" cy="160.7" r=".51" fill="#000080"/>
<circle cx="144.6" cy="160.7" r=".51" fill="none" stroke="#000080" stroke-width=".21"/>
<path d="M243.7 186.1v2.6" fill="none" stroke="#000080" stroke-width=".25"/>
<circle cx="243.7" cy="188.7" r=".51" fill="#000080"/>
<circle cx="243.7" cy="188.7" r=".51" fill="none" stroke="#000080" stroke-width=".21"/>
<path d="M233.5 186.1v2.6" fill="none" stroke="#000080" stroke-width=".25"/>
<circle cx="233.5" cy="188.7" r=".51" fill="#000080"/>
<circle cx="233.5" cy="188.7" r=".51" fill="none" stroke="#000080" stroke-width=".21"/>
<path d="M223.3 186.1v2.6" fill="none" stroke="#000080" stroke-width=".25"/>
<circle cx="223.3" cy="188.7" r=".51" fill="#000080"/>
<circle cx="223.3" cy="188.7" r=".51" fill="none" stroke="#000080" stroke-width=".21"/>
<path d="M144.6 120.1v5.1" fill="none" stroke="#000080" stroke-width=".25"/>
<circle cx="144.6" cy="120.1" r=".51" fill="#000080"/>
<circle cx="144.6" cy="120.1" r=".51" fill="none" stroke="#000080" stroke-width=".21"/>
<path d="M65.8 120.1v5.1h2.5M78.5 125.2h2.5" fill="none" stroke="#000080" stroke-width=".25"/>
<circle cx="65.8" cy="120.1" r=".51" fill="#000080"/>
<circle cx="65.8" cy="120.1" r=".51" fill="none" stroke="#000080" stroke-width=".21"/>
<path d="M121.7 137.9h12.7" fill="none" stroke="#000080" stroke-width=".25"/>
<circle cx="134.4" cy="137.9" r=".51" fill="#000080"/>
<circle cx="134.4" cy="137.9" r=".51" fill="none" stroke="#000080" stroke-width=".21"/>
<path d="M185.2 112.5h10.2M185.2 109.9h10.2M164.9 120.1h30.5M192.8 137.9h2.6" fill="none" stroke="#000080" stroke-width=".25"/>
<circle cx="192.8" cy="137.9" r=".51" fill="#000080"/>
<circle cx="192.8" cy="137.9" r=".51" fill="none" stroke="#000080" stroke-width=".21"/>
<path d="M241.1 107.4h5.1M241.1 127.7h2.6" fill="none" stroke="#000080" stroke-width=".25"/>
<circle cx="246.2" cy="107.4" r=".51" fill="#000080"/>
<circle cx="246.2" cy="107.4" r=".51" fill="none" stroke="#000080" stroke-width=".21"/>
<path d="M182.7 127.7v2.5M192.8 140.4v2.5M182.7 160.7v2.6" fill="none" stroke="#000080" stroke-width=".25"/>
<circle cx="192.8" cy="140.4" r=".51" fill="#000080"/>
<circle cx="192.8" cy="140.4" r=".51" fill="none" stroke="#000080" stroke-width=".21"/>
<path d="M192.8 104.9v2.5" fill="none" stroke="#000080" stroke-width=".25"/>
<circle cx="192.8" cy="107.4" r=".51" fill="#000080"/>
<circle cx="192.8" cy="107.4" r=".51" fill="none" stroke="#000080" stroke-width=".21"/>
<path d="M192.8 92.2v2.5M195.4 122.6h-7.6v22.9h-5.1" fill="none" stroke="#000080" stroke-width=".25"/>
<circle cx="187.8" cy="127.7" r=".51" fill="#000080"/>
<circle cx="187.8" cy="127.7" r=".51" fill="none" stroke="#000080" stroke-width=".21"/>
<circle cx="182.7" cy="145.5" r=".51" fill="#000080"/>
<circle cx="182.7" cy="145.5" r=".51" fill="none" stroke="#000080" stroke-width=".21"/>
<path d="M78.5 104.8v10.2h2.5" fill="none" stroke="#000080" stroke-width=".25"/>
<circle cx="78.5" cy="112.5" r=".51" fill="#000080"/>
<circle cx="78.5" cy="112.5" r=".51" fill="none" stroke="#000080" stroke-width=".21"/>
<circle cx="78.5" cy="109.9" r=".51" fill="#000080"/>
<circle cx="78.5" cy="109.9" r=".51" fill="none" stroke="#000080" stroke-width=".21"/>
<path d="M195.4 135.3h-2.6v5.1h2.6" fill="none" stroke="#000080" stroke-width=".25"/>
<circle cx="192.8" cy="137.9" r=".51" fill="#000080"/>
<circle cx="192.8" cy="137.9" r=".51" fill="none" stroke="#000080" stroke-width=".21"/>
<circle cx="192.8" cy="140.4" r=".51" fill="#000080"/>
<circle cx="192.8" cy="140.4" r=".51" fill="none" stroke="#000080" stroke-width=".21"/>
<path d="M246.2 104.9v5h-5.1M251.3 109.9v2.6h-10.2" fill="none" stroke="#000080" stroke-width=".25"/>
<circle cx="246.2" cy="107.4" r=".51" fill="#000080"/>
<circle cx="246.2" cy="107.4" r=".51" fill="none" stroke="#000080" stroke-width=".21"/>
<path d="M159.8 135.3v2.6h-2.5" fill="none" stroke="#000080" stroke-width=".25"/>
<circle cx="159.8" cy="137.9" r=".51" fill="#000080"/>
<circle cx="159.8" cy="137.9" r=".51" fill="none" stroke="#000080" stroke-width=".21"/>
<path d="M256.4 122.6v15.3h-2.6M271.6 120.1h2.6M271.6 122.6h2.6" fill="none" stroke="#000080" stroke-width=".25"/>
<circle cx="256.4" cy="122.6" r=".51" fill="#000080"/>
<circle cx="256.4" cy="122.6" r=".51" fill="none" stroke="#000080" stroke-width=".21"/>
<path d="M274.2 74.4v2.5" fill="none" stroke="#000080" stroke-width=".25"/>
<circle cx="274.2" cy="74.4" r=".51" fill="#000080"/>
<circle cx="274.2" cy="74.4" r=".51" fill="none" stroke="#000080" stroke-width=".21"/>
<path d="M258.9 74.4h-7.6v2.5" fill="none" stroke="#000080" stroke-width=".25"/>
<circle cx="258.9" cy="74.4" r=".51" fill="#000080"/>
<circle cx="258.9" cy="74.4" r=".51" fill="none" stroke="#000080" stroke-width=".21"/>
<path d="M266.6 74.4h-7.7v2.5" fill="none" stroke="#000080" stroke-width=".25"/>
<circle cx="258.9" cy="74.4" r=".51" fill="#000080"/>
<circle cx="258.9" cy="74.4" r=".51" fill="none" stroke="#000080" stroke-width=".21"/>
<circle cx="266.6" cy="74.4" r=".51" fill="#000080"/>
<circle cx="266.6" cy="74.4" r=".51" fill="none" stroke="#000080" stroke-width=".21"/>
<path d="M236.1 71.8v5.1M223.3 158.2h40.7v2.5" fill="none" stroke="#000080" stroke-width=".25"/>
<circle cx="223.3" cy="158.2" r=".51" fill="#000080"/>
<circle cx="223.3" cy="158.2" r=".51" fill="none" stroke="#000080" stroke-width=".21"/>
<circle cx="233.5" cy="158.2" r=".51" fill="#000080"/>
<circle cx="233.5" cy="158.2" r=".51" fill="none" stroke="#000080" stroke-width=".21"/>
<circle cx="243.7" cy="158.2" r=".51" fill="#000080"/>
<circle cx="243.7" cy="158.2" r=".51" fill="none" stroke="#000080" stroke-width=".21"/>
<circle cx="253.8" cy="158.2" r=".51" fill="#000080"/>
<circle cx="253.8" cy="158.2" r=".51" fill="none" stroke="#000080" stroke-width=".21"/>
<path d="M205.6 158.2h17.7v2.5" fill="none" stroke="#000080" stroke-width=".25"/>
<circle cx="213.2" cy="158.2" r=".51" fill="#000080"/>
<circle cx="213.2" cy="158.2" r=".51" fill="none" stroke="#000080" stroke-width=".21"/>
<circle cx="223.3" cy="158.2" r=".51" fill="#000080"/>
<circle cx="223.3" cy="158.2" r=".51" fill="none" stroke="#000080" stroke-width=".21"/>
<path d="M60.7 120.1h20.3" fill="none" stroke="#000080" stroke-width=".25"/>
<circle cx="65.8" cy="120.1" r=".51" fill="#000080"/>
<circle cx="65.8" cy="120.1" r=".51" fill="none" stroke="#000080" stroke-width=".21"/>
<path d="M121.7 142.9h7.6v2.6" fill="none" stroke="#000080" stroke-width=".25"/>
<circle cx="124.2" cy="142.9" r=".51" fill="#000080"/>
<circle cx="124.2" cy="142.9" r=".51" fill="none" stroke="#000080" stroke-width=".21"/>
<path d="M121.7 130.2h12.7v5.1h-12.7" fill="none" stroke="#000080" stroke-width=".25"/>
<circle cx="134.4" cy="135.3" r=".51" fill="#000080"/>
<circle cx="134.4" cy="135.3" r=".51" fill="none" stroke="#000080" stroke-width=".21"/>
<circle cx="134.4" cy="130.2" r=".51" fill="#000080"/>
<circle cx="134.4" cy="130.2" r=".51" fill="none" stroke="#000080" stroke-width=".21"/>
<path d="M134.4 135.3v2.6" fill="none" stroke="#000080" stroke-width=".25"/>
<circle cx="134.4" cy="137.9" r=".51" fill="#000080"/>
<circle cx="134.4" cy="137.9" r=".51" fill="none" stroke="#000080" stroke-width=".21"/>
<circle cx="134.4" cy="135.3" r=".51" fill="#000080"/>
<circle cx="134.4" cy="135.3" r=".51" fill="none" stroke="#000080" stroke-width=".21"/>
<path d="M134.4 137.9v2.5h-12.7" fill="none" stroke="#000080" stroke-width=".25"/>
<circle cx="134.4" cy="140.4" r=".51" fill="#000080"/>
<circle cx="134.4" cy="140.4" r=".51" fill="none" stroke="#000080" stroke-width=".21"/>
<circle cx="134.4" cy="137.9" r=".51" fill="#000080"/>
<circle cx="134.4" cy="137.9" r=".51" fill="none" stroke="#000080" stroke-width=".21"/>
<path d="M134.4 140.4v20.3" fill="none" stroke="#000080" stroke-width=".25"/>
<circle cx="134.4" cy="158.2" r=".51" fill="#000080"/>
<circle cx="134.4" cy="158.2" r=".51" fill="none" stroke="#000080" stroke-width=".21"/>
<circle cx="134.4" cy="140.4" r=".51" fill="#000080"/>
<circle cx="134.4" cy="140.4" r=".51" fill="none" stroke="#000080" stroke-width=".21"/>
<path d="M129.3 155.6v2.6h5.1" fill="none" stroke="#000080" stroke-width=".25"/>
<circle cx="134.4" cy="158.2" r=".51" fill="#000080"/>
<circle cx="134.4" cy="158.2" r=".51" fill="none" stroke="#000080" stroke-width=".21"/>
<path d="M121.7 120.1h33" fill="none" stroke="#000080" stroke-width=".25"/>
<circle cx="144.6" cy="120.1" r=".51" fill="#000080"/>
<circle cx="144.6" cy="120.1" r=".51" fill="none" stroke="#000080" stroke-width=".21"/>
<path d="M144.6 142.9h-5.1v30.5h-119.5v-7.6h17.8" fill="none" stroke="#000080" stroke-width=".25"/>
<circle cx="144.6" cy="142.9" r=".51" fill="#000080"/>
<circle cx="144.6" cy="142.9" r=".51" fill="none" stroke="#000080" stroke-width=".21"/>
<circle cx="20" cy="165.8" r=".51" fill="#000080"/>
<circle cx="20" cy="165.8" r=".51" fill="none" stroke="#000080" stroke-width=".21"/>
<path d="M20 148v17.8" fill="none" stroke="#000080" stroke-width=".25"/>
<circle cx="20" cy="165.8" r=".51" fill="#000080"/>
<circle cx="20" cy="165.8" r=".51" fill="none" stroke="#000080" stroke-width=".21"/>
<path d="M81 130.2h-7.6v12.7h-2.6" fill="none" stroke="#000080" stroke-width=".25"/>
<circle cx="73.4" cy="142.9" r=".51" fill="#000080"/>
<circle cx="73.4" cy="142.9" r=".51" fill="none" stroke="#000080" stroke-width=".21"/>
<path d="M144.6 158.2v5.1" fill="none" stroke="#000080" stroke-width=".25"/>
<circle cx="144.6" cy="160.7" r=".51" fill="#000080"/>
<circle cx="144.6" cy="160.7" r=".51" fill="none" stroke="#000080" stroke-width=".21"/>
<path d="M144.6 135.3v12.7" fill="none" stroke="#000080" stroke-width=".25"/>
<circle cx="144.6" cy="137.9" r=".51" fill="#000080"/>
<circle cx="144.6" cy="137.9" r=".51" fill="none" stroke="#000080" stroke-width=".21"/>
<circle cx="144.6" cy="142.9" r=".51" fill="#000080"/>
<circle cx="144.6" cy="142.9" r=".51" fill="none" stroke="#000080" stroke-width=".21"/>
<path d="M182.7 145.5v5.1" fill="none" stroke="#000080" stroke-width=".25"/>
<circle cx="182.7" cy="148" r=".51" fill="#000080"/>
<circle cx="182.7" cy="148" r=".51" fill="none" stroke="#000080" stroke-width=".21"/>
<circle cx="182.7" cy="145.5" r=".51" fill="#000080"/>
<circle cx="182.7" cy="145.5" r=".51" fill="none" stroke="#000080" stroke-width=".21"/>
<path d="M180.1 142.9h2.6" fill="none" stroke="#000080" stroke-width=".25"/>
<circle cx="182.7" cy="142.9" r=".51" fill="#000080"/>
<circle cx="182.7" cy="142.9" r=".51" fill="none" stroke="#000080" stroke-width=".21"/>
<path d="M182.7 140.4v5.1" fill="none" stroke="#000080" stroke-width=".25"/>
<circle cx="182.7" cy="145.5" r=".51" fill="#000080"/>
<circle cx="182.7" cy="145.5" r=".51" fill="none" stroke="#000080" stroke-width=".21"/>
<circle cx="182.7" cy="142.9" r=".51" fill="#000080"/>
<circle cx="182.7" cy="142.9" r=".51" fill="none" stroke="#000080" stroke-width=".21"/>
<path d="M258.9 120.1v17.8h2.6" fill="none" stroke="#000080" stroke-width=".25"/>
<circle cx="258.9" cy="120.1" r=".51" fill="#000080"/>
<circle cx="258.9" cy="120.1" r=".51" fill="none" stroke="#000080" stroke-width=".21"/>
<path d="M241.1 122.6h20.4" fill="none" stroke="#000080" stroke-width=".25"/>
<circle cx="256.4" cy="122.6" r=".51" fill="#000080"/>
<circle cx="256.4" cy="122.6" r=".51" fill="none" stroke="#000080" stroke-width=".21"/>
<path d="M241.1 120.1h20.4" fill="none" stroke="#000080" stroke-width=".25"/>
<circle cx="258.9" cy="120.1" r=".51" fill="#000080"/>
<circle cx="258.9" cy="120.1" r=".51" fill="none" stroke="#000080" stroke-width=".21"/>
<path d="M264 170.9v5.1" fill="none" stroke="#000080" stroke-width=".25"/>
<circle cx="264" cy="173.4" r=".51" fill="#000080"/>
<circle cx="264" cy="173.4" r=".51" fill="none" stroke="#000080" stroke-width=".21"/>
<path d="M253.8 173.4h10.2" fill="none" stroke="#000080" stroke-width=".25"/>
<circle cx="264" cy="173.4" r=".51" fill="#000080"/>
<circle cx="264" cy="173.4" r=".51" fill="none" stroke="#000080" stroke-width=".21"/>
<circle cx="253.8" cy="173.4" r=".51" fill="#000080"/>
<circle cx="253.8" cy="173.4" r=".51" fill="none" stroke="#000080" stroke-width=".21"/>
<path d="M243.7 173.4h10.1" fill="none" stroke="#000080" stroke-width=".25"/>
<circle cx="253.8" cy="173.4" r=".51" fill="#000080"/>
<circle cx="253.8" cy="173.4" r=".51" fill="none" stroke="#000080" stroke-width=".21"/>
<circle cx="243.7" cy="173.4" r=".51" fill="#000080"/>
<circle cx="243.7" cy="173.4" r=".51" fill="none" stroke="#000080" stroke-width=".21"/>
<path d="M233.5 173.4h10.2" fill="none" stroke="#000080" stroke-width=".25"/>
<circle cx="243.7" cy="173.4" r=".51" fill="#000080"/>
<circle cx="243.7" cy="173.4" r=".51" fill="none" stroke="#000080" stroke-width=".21"/>
<circle cx="233.5" cy="173.4" r=".51" fill="#000080"/>
<circle cx="233.5" cy="173.4" r=".51" fill="none" stroke="#000080" stroke-width=".21"/>
<path d="M223.3 173.4h10.2" fill="none" stroke="#000080" stroke-width=".25"/>
<circle cx="233.5" cy="173.4" r=".51" fill="#000080"/>
<circle cx="233.5" cy="173.4" r=".51" fill="none" stroke="#000080" stroke-width=".21"/>
<circle cx="223.3" cy="173.4" r=".51" fill="#000080"/>
<circle cx="223.3" cy="173.4" r=".51" fill="none" stroke="#000080" stroke-width=".21"/>
<path d="M213.2 173.4h10.1" fill="none" stroke="#000080" stroke-width=".25"/>
<circle cx="223.3" cy="173.4" r=".51" fill="#000080"/>
<circle cx="223.3" cy="173.4" r=".51" fill="none" stroke="#000080" stroke-width=".21"/>
<circle cx="213.2" cy="173.4" r=".51" fill="#000080"/>
<circle cx="213.2" cy="173.4" r=".51" fill="none" stroke="#000080" stroke-width=".21"/>
<path d="M208.1 173.4h5.1" fill="none" stroke="#000080" stroke-width=".25"/>
<circle cx="213.2" cy="173.4" r=".51" fill="#000080"/>
<circle cx="213.2" cy="173.4" r=".51" fill="none" stroke="#000080" stroke-width=".21"/>
<path d="M264 186.1v2.6h-58.4" fill="none" stroke="#000080" stroke-width=".25"/>
<circle cx="213.2" cy="188.7" r=".51" fill="#000080"/>
<circle cx="213.2" cy="188.7" r=".51" fill="none" stroke="#000080" stroke-width=".21"/>
<circle cx="223.3" cy="188.7" r=".51" fill="#000080"/>
<circle cx="223.3" cy="188.7" r=".51" fill="none" stroke="#000080" stroke-width=".21"/>
<circle cx="233.5" cy="188.7" r=".51" fill="#000080"/>
<circle cx="233.5" cy="188.7" r=".51" fill="none" stroke="#000080" stroke-width=".21"/>
<circle cx="243.7" cy="188.7" r=".51" fill="#000080"/>
<circle cx="243.7" cy="188.7" r=".51" fill="none" stroke="#000080" stroke-width=".21"/>
<circle cx="253.8" cy="188.7" r=".51" fill="#000080"/>
<circle cx="253.8" cy="188.7" r=".51" fill="none" stroke="#000080" stroke-width=".21"/>
<path d="M213.2 186.1v2.6" fill="none" stroke="#000080" stroke-width=".25"/>
<circle cx="213.2" cy="188.7" r=".51" fill="#000080"/>
<circle cx="213.2" cy="188.7" r=".51" fill="none" stroke="#000080" stroke-width=".21"/>
<path d="M253.8 186.1v2.6" fill="none" stroke="#000080" stroke-width=".25"/>
<circle cx="253.8" cy="188.7" r=".51" fill="#000080"/>
<circle cx="253.8" cy="188.7" r=".51" fill="none" stroke="#000080" stroke-width=".21"/>
<path d="M213.2 170.9v5.1" fill="none" stroke="#000080" stroke-width=".25"/>
<circle cx="213.2" cy="173.4" r=".51" fill="#000080"/>
<circle cx="213.2" cy="173.4" r=".51" fill="none" stroke="#000080" stroke-width=".21"/>
<path d="M223.3 170.9v5.1" fill="none" stroke="#000080" stroke-width=".25"/>
<circle cx="223.3" cy="173.4" r=".51" fill="#000080"/>
<circle cx="223.3" cy="173.4" r=".51" fill="none" stroke="#000080" stroke-width=".21"/>
<path d="M233.5 170.9v5.1" fill="none" stroke="#000080" stroke-width=".25"/>
<circle cx="233.5" cy="173.4" r=".51" fill="#000080"/>
<circle cx="233.5" cy="173.4" r=".51" fill="none" stroke="#000080" stroke-width=".21"/>
<path d="M243.7 170.9v5.1" fill="none" stroke="#000080" stroke-width=".25"/>
<circle cx="243.7" cy="173.4" r=".51" fill="#000080"/>
<circle cx="243.7" cy="173.4" r=".51" fill="none" stroke="#000080" stroke-width=".21"/>
<path d="M253.8 170.9v5.1" fill="none" stroke="#000080" stroke-width=".25"/>
<circle cx="253.8" cy="173.4" r=".51" fill="#000080"/>
<circle cx="253.8" cy="173.4" r=".51" fill="none" stroke="#000080" stroke-width=".21"/>
<path d="M185.2 107.4h10.2" fill="none" stroke="#000080" stroke-width=".25"/>
<circle cx="187.8" cy="107.4" r=".51" fill="#000080"/>
<circle cx="187.8" cy="107.4" r=".51" fill="none" stroke="#000080" stroke-width=".21"/>
<circle cx="192.8" cy="107.4" r=".51" fill="#000080"/>
<circle cx="192.8" cy="107.4" r=".51" fill="none" stroke="#000080" stroke-width=".21"/>
<path d="M116.6 54.1v12.7" fill="none" stroke="#000080" stroke-width=".25"/>
<circle cx="116.6" cy="56.6" r=".51" fill="#000080"/>
<circle cx="116.6" cy="56.6" r=".51" fill="none" stroke="#000080" stroke-width=".21"/>
<path d="M111.5 28.7v10.1h5.1v5.1" fill="none" stroke="#000080" stroke-width=".25"/>
<circle cx="111.5" cy="28.7" r=".51" fill="#000080"/>
<circle cx="111.5" cy="28.7" r=".51" fill="none" stroke="#000080" stroke-width=".21"/>
<path d="M124.2 28.7h2.6v10.1h-5.1v5.1" fill="none" stroke="#000080" stroke-width=".25"/>
<circle cx="126.8" cy="28.7" r=".51" fill="#000080"/>
<circle cx="126.8" cy="28.7" r=".51" fill="none" stroke="#000080" stroke-width=".21"/>
<path d="M25.1 61.7h5.1" fill="none" stroke="#000080" stroke-width=".25"/>
<circle cx="30.2" cy="61.7" r=".51" fill="#000080"/>
<circle cx="30.2" cy="61.7" r=".51" fill="none" stroke="#000080" stroke-width=".21"/>
<circle cx="27.6" cy="61.7" r=".51" fill="#000080"/>
<circle cx="27.6" cy="61.7" r=".51" fill="none" stroke="#000080" stroke-width=".21"/>
<path d="M32.7 61.7h-2.5v2.5" fill="none" stroke="#000080" stroke-width=".25"/>
<circle cx="30.2" cy="61.7" r=".51" fill="#000080"/>
<circle cx="30.2" cy="61.7" r=".51" fill="none" stroke="#000080" stroke-width=".21"/>
<path d="M40.3 46.4v2.6h12.8v7.6M30.2 74.4v2.5M42.9 61.7h2.5M53.1 66.8v10.1M60.7 74.4v2.5" fill="none" stroke="#000080" stroke-width=".25"/>
<circle cx="53.1" cy="49" r=".51" fill="#000080"/>
<circle cx="53.1" cy="49" r=".51" fill="none" stroke="#000080" stroke-width=".21"/>
<path d="M58.1 49h5.1" fill="none" stroke="#000080" stroke-width=".25"/>
<circle cx="60.7" cy="49" r=".51" fill="#000080"/>
<circle cx="60.7" cy="49" r=".51" fill="none" stroke="#000080" stroke-width=".21"/>
<path d="M60.7 28.7v5" fill="none" stroke="#000080" stroke-width=".25"/>
<circle cx="60.7" cy="28.7" r=".51" fill="#000080"/>
<circle cx="60.7" cy="28.7" r=".51" fill="none" stroke="#000080" stroke-width=".21"/>
<path d="M58.1 59.1h5.1" fill="none" stroke="#000080" stroke-width=".25"/>
<circle cx="60.7" cy="59.1" r=".51" fill="#000080"/>
<circle cx="60.7" cy="59.1" r=".51" fill="none" stroke="#000080" stroke-width=".21"/>
<path d="M65.8 33.7h2.5v15.3" fill="none" stroke="#000080" stroke-width=".25"/>
<circle cx="68.3" cy="49" r=".51" fill="#000080"/>
<circle cx="68.3" cy="49" r=".51" fill="none" stroke="#000080" stroke-width=".21"/>
<path d="M281.8 71.8v2.6h-15.2v2.5" fill="none" stroke="#000080" stroke-width=".25"/>
<circle cx="266.6" cy="74.4" r=".51" fill="#000080"/>
<circle cx="266.6" cy="74.4" r=".51" fill="none" stroke="#000080" stroke-width=".21"/>
<circle cx="274.2" cy="74.4" r=".51" fill="#000080"/>
<circle cx="274.2" cy="74.4" r=".51" fill="none" stroke="#000080" stroke-width=".21"/>
<path d="M65.8 49h2.5" fill="none" stroke="#000080" stroke-width=".25"/>
<circle cx="68.3" cy="49" r=".51" fill="#000080"/>
<circle cx="68.3" cy="49" r=".51" fill="none" stroke="#000080" stroke-width=".21"/>
<path d="M68.3 49v27.9" fill="none" stroke="#000080" stroke-width=".25"/>
<circle cx="68.3" cy="49" r=".51" fill="#000080"/>
<circle cx="68.3" cy="49" r=".51" fill="none" stroke="#000080" stroke-width=".21"/>
<path d="M91.2 64.2v7.6h-5.1" fill="none" stroke="#000080" stroke-width=".25"/>
<circle cx="86.1" cy="71.8" r=".51" fill="#000080"/>
<circle cx="86.1" cy="71.8" r=".51" fill="none" stroke="#000080" stroke-width=".21"/>
<path d="M81 56.6v5.1M81 71.8v2.6h5.1" fill="none" stroke="#000080" stroke-width=".25"/>
<circle cx="86.1" cy="74.4" r=".51" fill="#000080"/>
<circle cx="86.1" cy="74.4" r=".51" fill="none" stroke="#000080" stroke-width=".21"/>
<path d="M182.7 148h-10.2v2.6" fill="none" stroke="#000080" stroke-width=".25"/>
<circle cx="182.7" cy="148" r=".51" fill="#000080"/>
<circle cx="182.7" cy="148" r=".51" fill="none" stroke="#000080" stroke-width=".21"/>
<path d="M159.8 41.4h7.6v15.2M172.5 160.7v2.6" fill="none" stroke="#000080" stroke-width=".25"/>
<circle cx="167.4" cy="51.5" r=".51" fill="#000080"/>
<circle cx="167.4" cy="51.5" r=".51" fill="none" stroke="#000080" stroke-width=".21"/>
<path d="M159.8 31.2h7.6" fill="none" stroke="#000080" stroke-width=".25"/>
<circle cx="164.9" cy="31.2" r=".51" fill="#000080"/>
<circle cx="164.9" cy="31.2" r=".51" fill="none" stroke="#000080" stroke-width=".21"/>
<path d="M192.8 31.2h17.8" fill="none" stroke="#000080" stroke-width=".25"/>
<circle cx="195.4" cy="31.2" r=".51" fill="#000080"/>
<circle cx="195.4" cy="31.2" r=".51" fill="none" stroke="#000080" stroke-width=".21"/>
<circle cx="200.5" cy="31.2" r=".51" fill="#000080"/>
<circle cx="200.5" cy="31.2" r=".51" fill="none" stroke="#000080" stroke-width=".21"/>
<circle cx="208.1" cy="31.2" r=".51" fill="#000080"/>
<circle cx="208.1" cy="31.2" r=".51" fill="none" stroke="#000080" stroke-width=".21"/>
<path d="M220.8 28.7h25.4" fill="none" stroke="#000080" stroke-width=".25"/>
<circle cx="231" cy="28.7" r=".51" fill="#000080"/>
<circle cx="231" cy="28.7" r=".51" fill="none" stroke="#000080" stroke-width=".21"/>
<path d="M208.1 59.1v7.7" fill="none" stroke="#000080" stroke-width=".25"/>
<circle cx="208.1" cy="61.7" r=".51" fill="#000080"/>
<circle cx="208.1" cy="61.7" r=".51" fill="none" stroke="#000080" stroke-width=".21"/>
<path d="M208.1 31.2v17.8" fill="none" stroke="#000080" stroke-width=".25"/>
<circle cx="208.1" cy="46.4" r=".51" fill="#000080"/>
<circle cx="208.1" cy="46.4" r=".51" fill="none" stroke="#000080" stroke-width=".21"/>
<circle cx="208.1" cy="31.2" r=".51" fill="#000080"/>
<circle cx="208.1" cy="31.2" r=".51" fill="none" stroke="#000080" stroke-width=".21"/>
<path d="M40.3 33.7v2.6" fill="none" stroke="#000080" stroke-width=".25"/>
<circle cx="40.3" cy="33.7" r=".51" fill="#000080"/>
<circle cx="40.3" cy="33.7" r=".51" fill="none" stroke="#000080" stroke-width=".21"/>
<path d="M37.8 33.7h15.3" fill="none" stroke="#000080" stroke-width=".25"/>
<circle cx="40.3" cy="33.7" r=".51" fill="#000080"/>
<circle cx="40.3" cy="33.7" r=".51" fill="none" stroke="#000080" stroke-width=".21"/>
<path d="M86.1 46.4h5.1v7.7" fill="none" stroke="#000080" stroke-width=".25"/>
<circle cx="86.1" cy="46.4" r=".51" fill="#000080"/>
<circle cx="86.1" cy="46.4" r=".51" fill="none" stroke="#000080" stroke-width=".21"/>
<path d="M86.1 41.4v12.7" fill="none" stroke="#000080" stroke-width=".25"/>
<circle cx="86.1" cy="46.4" r=".51" fill="#000080"/>
<circle cx="86.1" cy="46.4" r=".51" fill="none" stroke="#000080" stroke-width=".21"/>
<circle cx="86.1" cy="43.9" r=".51" fill="#000080"/>
<circle cx="86.1" cy="43.9" r=".51" fill="none" stroke="#000080" stroke-width=".21"/>
<path d="M86.1 43.9h-5.1v2.5" fill="none" stroke="#000080" stroke-width=".25"/>
<circle cx="86.1" cy="43.9" r=".51" fill="#000080"/>
<circle cx="86.1" cy="43.9" r=".51" fill="none" stroke="#000080" stroke-width=".21"/>
<path d="M86.1 64.2v12.7" fill="none" stroke="#000080" stroke-width=".25"/>
<circle cx="86.1" cy="74.4" r=".51" fill="#000080"/>
<circle cx="86.1" cy="74.4" r=".51" fill="none" stroke="#000080" stroke-width=".21"/>
<circle cx="86.1" cy="71.8" r=".51" fill="#000080"/>
<circle cx="86.1" cy="71.8" r=".51" fill="none" stroke="#000080" stroke-width=".21"/>
<path d="M103.9 28.7h7.6" fill="none" stroke="#000080" stroke-width=".25"/>
<circle cx="111.5" cy="28.7" r=".51" fill="#000080"/>
<circle cx="111.5" cy="28.7" r=".51" fill="none" stroke="#000080" stroke-width=".21"/>
<path d="M111.5 28.7h2.6" fill="none" stroke="#000080" stroke-width=".25"/>
<circle cx="111.5" cy="28.7" r=".51" fill="#000080"/>
<circle cx="111.5" cy="28.7" r=".51" fill="none" stroke="#000080" stroke-width=".21"/>
<path d="M20 28.7h73.7" fill="none" stroke="#000080" stroke-width=".25"/>
<circle cx="60.7" cy="28.7" r=".51" fill="#000080"/>
<circle cx="60.7" cy="28.7" r=".51" fill="none" stroke="#000080" stroke-width=".21"/>
<circle cx="86.1" cy="28.7" r=".51" fill="#000080"/>
<circle cx="86.1" cy="28.7" r=".51" fill="none" stroke="#000080" stroke-width=".21"/>
<use href="#words"/>
</svg>
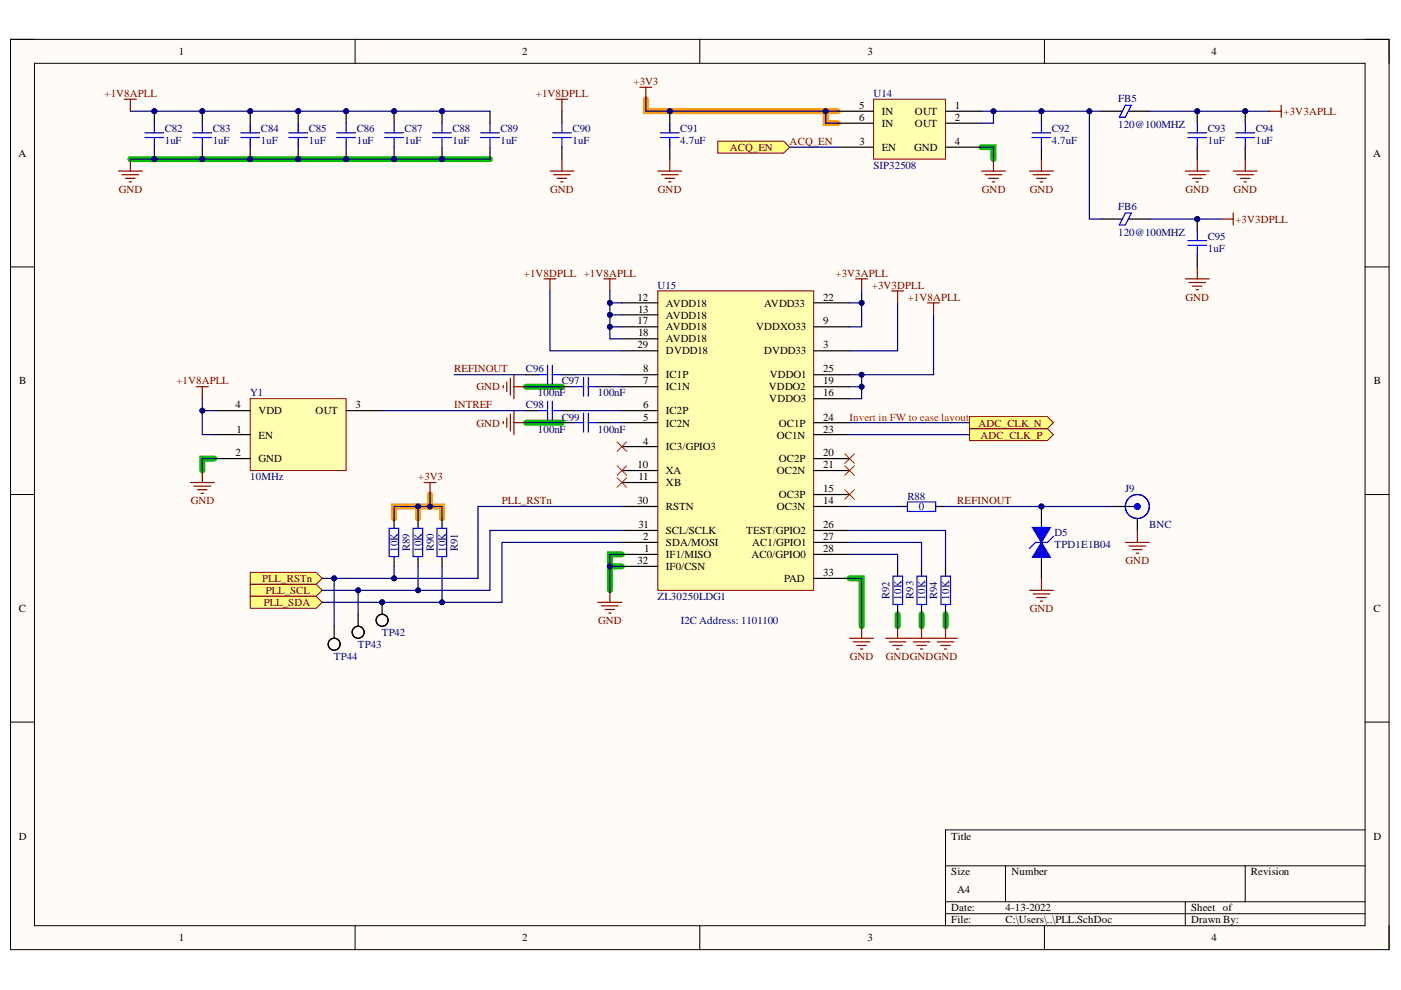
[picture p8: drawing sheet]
<svg xmlns="http://www.w3.org/2000/svg" width="297mm" height="210mm" viewBox="0 0 297 210" stroke-linecap="round" stroke-linejoin="round" font-family="sans-serif">
<defs><g id="words">
<g font-size="2.3">
<text x="37.9" y="11.7">1</text>
<text x="110.7" y="11.7">2</text>
<text x="183.9" y="11.7">3</text>
<text x="256.8" y="11.7">4</text>
<text x="182.1" y="23.1">5</text>
<text x="202.4" y="23.1">1</text>
<text x="182.1" y="25.6">6</text>
<text x="187" y="24.3">IN</text>
<text x="187" y="26.9">IN</text>
<text x="194" y="24.3">OUT</text>
<text x="194" y="26.9">OUT</text>
<text x="202.4" y="25.6">2</text>
<text x="3.9" y="33.3">A</text>
<text x="182.2" y="30.8">3</text>
<text x="187" y="32">EN</text>
<text x="193.8" y="32">GND</text>
<text x="202.4" y="30.8">4</text>
<text x="291.1" y="33.3">A</text>
<text x="135.2" y="63.7">12</text>
<text x="141.2" y="65">AVDD18</text>
<text x="162" y="65">AVDD33</text>
<text x="174.5" y="63.7">22</text>
<text x="135.2" y="68.8">17</text>
<text x="135.3" y="66.3">13</text>
<text x="135.3" y="71.3">18</text>
<text x="141.2" y="67.5">AVDD18</text>
<text x="141.2" y="70.1">AVDD18</text>
<text x="160.3" y="70.1">VDDXO33</text>
<text x="174.5" y="68.8">9</text>
<text x="135.2" y="73.9">29</text>
<text x="141.2" y="72.6">AVDD18</text>
<text x="141.2" y="75.1">DVDD18</text>
<text x="162" y="75.1">DVDD33</text>
<text x="174.5" y="73.9">3</text>
<text x="4.1" y="81.5">B</text>
<text x="136.4" y="81.5">7</text>
<text x="136.4" y="78.9">8</text>
<text x="141.2" y="82.7">IC1N</text>
<text x="141.2" y="80.2">IC1P</text>
<text x="163" y="82.7">VDDO2</text>
<text x="163.2" y="80.2">VDDO1</text>
<text x="174.5" y="81.5">19</text>
<text x="174.5" y="78.9">25</text>
<text x="291.3" y="81.5">B</text>
<text x="49.9" y="86.6">4</text>
<text x="54.8" y="87.8">VDD</text>
<text x="66.9" y="87.8">OUT</text>
<text x="75.4" y="86.6">3</text>
<text x="136.4" y="89.2">5</text>
<text x="136.4" y="86.6">6</text>
<text x="141.2" y="87.8">IC2P</text>
<text x="163.1" y="85.3">VDDO3</text>
<text x="174.5" y="84">16</text>
<text x="174.5" y="89.2">24</text>
<text x="50.2" y="91.7">1</text>
<text x="54.8" y="93">EN</text>
<text x="136.4" y="94.2">4</text>
<text x="141.2" y="95.5">IC3/GPIO3</text>
<text x="141.2" y="90.4">IC2N</text>
<text x="164.7" y="93">OC1N</text>
<text x="165.1" y="90.4">OC1P</text>
<text x="174.5" y="91.7">23</text>
<text x="49.9" y="96.8">2</text>
<text x="54.8" y="98">GND</text>
<text x="135.2" y="99.3">10</text>
<text x="135.4" y="101.9">11</text>
<text x="141.2" y="100.6">XA</text>
<text x="164.7" y="100.6">OC2N</text>
<text x="165.1" y="98">OC2P</text>
<text x="174.5" y="96.8">20</text>
<text x="174.5" y="99.3">21</text>
<text x="135.2" y="106.9">30</text>
<text x="141.2" y="103.1">XB</text>
<text x="165.1" y="105.7">OC3P</text>
<text x="174.5" y="106.9">14</text>
<text x="174.5" y="104.4">15</text>
<text x="135.4" y="112">31</text>
<text x="141.2" y="108.2">RSTN</text>
<text x="141.2" y="113.3">SCL/SCLK</text>
<text x="158.2" y="113.3">TEST/GPIO2</text>
<text x="164.7" y="108.2">OC3N</text>
<text x="174.5" y="112">26</text>
<text x="135.2" y="119.6">32</text>
<text x="136.4" y="114.5">2</text>
<text x="136.5" y="117.1">1</text>
<text x="141.2" y="118.3">IF1/MISO</text>
<text x="141.2" y="115.8">SDA/MOSI</text>
<text x="159.3" y="118.3">AC0/GPIO0</text>
<text x="159.5" y="115.8">AC1/GPIO1</text>
<text x="174.5" y="114.5">27</text>
<text x="174.5" y="117.1">28</text>
<text x="141.2" y="120.9">IF0/CSN</text>
<text x="166.2" y="123.4">PAD</text>
<text x="174.5" y="122.1">33</text>
<text x="4" y="129.7">C</text>
<text x="291.2" y="129.7">C</text>
<text x="4" y="178">D</text>
<text x="201.7" y="178">Title</text>
<text x="291.2" y="178">D</text>
<text x="201.7" y="185.6">Size</text>
<text x="214.5" y="185.6">Number</text>
<text x="265.2" y="185.6">Revision</text>
<text x="203" y="189.4">A4</text>
<text x="201.7" y="193.2">Date:</text>
<text x="201.7" y="195.8">File:</text>
<text x="213.2" y="193.2">4-13-2022</text>
<text x="213.2" y="195.8">C:\Users\..\PLL.SchDoc</text>
<text x="252.5" y="193.2">Sheet of</text>
<text x="252.5" y="195.8">Drawn By:</text>
<text x="37.9" y="199.6">1</text>
<text x="110.7" y="199.6">2</text>
<text x="183.9" y="199.6">3</text>
<text x="256.8" y="199.6">4</text>
</g>
<g font-size="2.3" fill="#800000">
<text x="134.3" y="18">+3V3</text>
<text x="22.2" y="20.5">+1V8APLL</text>
<text x="113.6" y="20.5">+1V8DPLL</text>
<text x="272.2" y="24.3">+3V3APLL</text>
<text x="154.7" y="32">ACQ_EN</text>
<text x="167.4" y="30.8">ACQ_EN</text>
<text x="25.2" y="40.9">GND</text>
<text x="116.7" y="40.9">GND</text>
<text x="139.5" y="40.9">GND</text>
<text x="208.2" y="40.9">GND</text>
<text x="218.4" y="40.9">GND</text>
<text x="251.3" y="40.9">GND</text>
<text x="261.5" y="40.9">GND</text>
<text x="261.9" y="47.2">+3V3DPLL</text>
<text x="111.1" y="58.7">+1V8DPLL +1V8APLL</text>
<text x="177.2" y="58.7">+3V3APLL</text>
<text x="184.9" y="61.2">+3V3DPLL</text>
<text x="192.5" y="63.7">+1V8APLL</text>
<text x="251.3" y="63.7">GND</text>
<text x="37.4" y="81.5">+1V8APLL</text>
<text x="96.3" y="78.9">REFINOUT</text>
<text x="101" y="82.7">GND</text>
<text x="96.3" y="86.6">INTREF</text>
<text x="101" y="90.4">GND</text>
<text x="207.4" y="90.4">ADC_CLK_N</text>
<text x="207.9" y="93">ADC_CLK_P</text>
<text x="88.7" y="101.9">+3V3</text>
<text x="40.4" y="106.9">GND</text>
<text x="106.4" y="106.9">PLL_RSTn</text>
<text x="203" y="106.9">REFINOUT</text>
<text x="238.7" y="119.6">GND</text>
<text x="55.6" y="123.4">PLL_RSTn</text>
<text x="56.3" y="125.9">PLL_SCL</text>
<text x="55.9" y="128.5">PLL_SDA</text>
<text x="218.4" y="129.7">GND</text>
<text x="126.8" y="132.3">GND</text>
<text x="180.2" y="139.9">GND</text>
<text x="187.8" y="139.9">GNDGNDGND</text>
</g>
<g font-size="2.3" fill="#000080">
<text x="185.2" y="20.5">U14</text>
<text x="237" y="21.5">FB5</text>
<text x="34.9" y="27.9">C82</text>
<text x="45.1" y="27.9">C83</text>
<text x="55.3" y="27.9">C84</text>
<text x="65.5" y="27.9">C85</text>
<text x="75.6" y="27.9">C86</text>
<text x="85.8" y="27.9">C87</text>
<text x="95.9" y="27.9">C88</text>
<text x="106.1" y="27.9">C89</text>
<text x="121.4" y="27.9">C90</text>
<text x="144.2" y="27.9">C91</text>
<text x="223" y="27.9">C92</text>
<text x="237" y="27.1">120@100MHZ</text>
<text x="256.1" y="27.9">C93</text>
<text x="266.2" y="27.9">C94</text>
<text x="34.9" y="30.5">1uF</text>
<text x="45.1" y="30.5">1uF</text>
<text x="55.3" y="30.5">1uF</text>
<text x="65.5" y="30.5">1uF</text>
<text x="75.6" y="30.5">1uF</text>
<text x="85.8" y="30.5">1uF</text>
<text x="95.9" y="30.5">1uF</text>
<text x="106.1" y="30.5">1uF</text>
<text x="121.4" y="30.5">1uF</text>
<text x="144.2" y="30.5">4.7uF</text>
<text x="185.2" y="35.8">SIP32508</text>
<text x="223" y="30.5">4.7uF</text>
<text x="256.1" y="30.5">1uF</text>
<text x="266.2" y="30.5">1uF</text>
<text x="237" y="44.5">FB6</text>
<text x="237" y="50">120@100MHZ</text>
<text x="256.1" y="50.8">C95</text>
<text x="256.1" y="53.3">1uF</text>
<text x="139.4" y="61.2">U15</text>
<text x="111.5" y="78.9">C96</text>
<text x="119.1" y="81.5">C97</text>
<text x="53" y="84">Y1</text>
<text x="111.5" y="86.6">C98</text>
<text x="114" y="84">100nF</text>
<text x="119.1" y="89.2">C99</text>
<text x="126.7" y="84">100nF</text>
<text x="114" y="91.7">100nF</text>
<text x="126.7" y="91.7">100nF</text>
<text x="53" y="101.9">10MHz</text>
<text x="192.4" y="105.9">R88</text>
<text x="238.6" y="104.4">J9</text>
<text x="194.8" y="108.2">0</text>
<text x="223.6" y="113.6">D5</text>
<text x="243.6" y="112">BNC</text>
<text x="84.3" y="117" transform="rotate(-90 84.3 117)">10K</text>
<text x="86.9" y="116.9" transform="rotate(-90 86.9 116.9)">R89</text>
<text x="89.4" y="117" transform="rotate(-90 89.4 117)">10K</text>
<text x="92" y="116.9" transform="rotate(-90 92 116.9)">R90</text>
<text x="94.5" y="117" transform="rotate(-90 94.5 117)">10K</text>
<text x="97" y="116.8" transform="rotate(-90 97 116.8)">R91</text>
<text x="223.6" y="116.1">TPD1E1B04</text>
<text x="139.4" y="127.2">ZL30250LDG1</text>
<text x="188.6" y="127" transform="rotate(-90 188.6 127)">R92</text>
<text x="191.1" y="127.1" transform="rotate(-90 191.1 127.1)">10K</text>
<text x="193.6" y="127" transform="rotate(-90 193.6 127)">R93</text>
<text x="196.2" y="127.1" transform="rotate(-90 196.2 127.1)">10K</text>
<text x="198.7" y="127" transform="rotate(-90 198.7 127)">R94</text>
<text x="201.3" y="127.1" transform="rotate(-90 201.3 127.1)">10K</text>
<text x="75.9" y="137.4">TP43</text>
<text x="81" y="134.8">TP42</text>
<text x="144.3" y="132.3">I2C Address: 1101100</text>
<text x="70.8" y="139.9">TP44</text>
</g>
<text font-size="2.3" fill="#f00" x="180.1" y="89.2">Invert in FW to ease layout</text>
</g></defs>
<path d="M2.2 8.3h292.3v193h-292.3z" fill-rule="evenodd" fill="#fffcf8"/>
<path d="M2.2 8.3h292.3v193h-292.3z" fill="none" stroke="#000" stroke-width=".21"/>
<path d="M7.3 13.4h282.1v182.9h-282.1z" fill-rule="evenodd" fill="#fffcf8"/>
<g fill="none" stroke="#000" stroke-width=".21">
<path d="M2.2 8.3h5.1M7.3 13.4h282.1v182.9h-282.1zM75.3 8.3v5.1M148.4 8.3v5.1M221.4 8.3v5.1M289.4 8.3h5.1v5.1M2.2 56.6h5.1M289.4 56.6h5.1M2.2 104.8h5.1M289.4 104.9h5.1M2.2 153.1h5.1M289.4 153.1h5.1"/>
<path d="M289.4 176h-88.9v20.3M75.3 196.3v5M148.4 196.3v5M200.5 183.6h88.9M200.5 191.2h88.9M200.5 193.7h88.9M213.2 183.6v7.6M221.4 196.3v5M251.3 191.2v5.1M264 183.6v7.6M294.5 196.3v5"/>
</g>
<path d="M136.9 21v2.6h40.7M175.1 23.6v2.5h2.5M88.6 107.4h-5v2.5M91.2 107.4h-2.6v2.5M91.2 104.8v2.6h2.5v2.5" fill="none" stroke="#f90" stroke-width="1.3"/>
<path d="M27.6 33.7h76.3M208.1 31.2h2.5v2.5M45.4 97.2h-2.5v2.6M111.5 82h7.6M111.5 89.6h7.6M131.8 117.5h-2.5v7.7M129.3 120.1h2.5M180.1 122.6h2.6v10.2M190.3 130.2v2.6M195.4 130.2v2.6M200.5 130.2v2.6" fill="none" stroke="#00be00" stroke-width="1.3"/>
<path d="M88.6 109.9v2M88.6 118.1v2M93.7 109.9v2M93.7 118.1v2" fill="none" stroke="#000" stroke-width=".25"/>
<path d="M87.6 112h2v6h-2zM92.7 112h2v6h-2z" fill="none" stroke="#00f" stroke-width=".25"/>
<path d="M89.9 102.3h2.6M91.2 102.3v2.5" fill="none" stroke="#800000" stroke-width=".25"/>
<path d="M53.1 121.4h13.9l1.3 1.2-1.3 1.3h-13.9z" fill-rule="evenodd" fill="#ffff80"/>
<path d="M53.1 121.4h13.9l1.3 1.2-1.3 1.3h-13.9z" fill="none" stroke="#800000" stroke-width=".21"/>
<circle cx="81" cy="127.7" r=".51" fill="#000080"/>
<circle cx="81" cy="127.7" r=".51" fill="none" stroke="#000080" stroke-width=".21"/>
<path d="M81 127.7v2.5" fill="none" stroke="#000" stroke-width=".25"/>
<circle cx="81" cy="127.7" r=".51" fill="#000080"/>
<circle cx="81" cy="127.7" r=".51" fill="none" stroke="#000080" stroke-width=".21"/>
<circle cx="81" cy="131.5" r="1.27" fill="none" stroke="#000" stroke-width=".25"/>
<path d="M185.2 21h15.3v12.7h-15.3z" fill-rule="evenodd" fill="#ffffb0"/>
<path d="M185.2 21h15.3v12.7h-15.3z" fill="none" stroke="#800000" stroke-width=".21"/>
<path d="M177.6 23.6h7.6M177.6 26.1h7.6M177.6 31.2h7.6M200.5 23.6h7.6M200.5 26.1h7.6M200.5 31.2h7.6" fill="none" stroke="#000" stroke-width=".25"/>
<path d="M135.7 18.5h2.5M136.9 18.5v2.5M208.1 36.3h5.1M208.9 37h3.5M209.6 37.8h2.1M210.4 38.6h.5M210.6 33.7v2.6" fill="none" stroke="#800000" stroke-width=".25"/>
<circle cx="142" cy="23.6" r=".51" fill="#000080"/>
<circle cx="142" cy="23.6" r=".51" fill="none" stroke="#000080" stroke-width=".21"/>
<path d="M142 23.6v2.5M142 31.2v2.5" fill="none" stroke="#000" stroke-width=".25"/>
<circle cx="142" cy="23.6" r=".51" fill="#000080"/>
<circle cx="142" cy="23.6" r=".51" fill="none" stroke="#000080" stroke-width=".21"/>
<path d="M140 29.2h4M140 28.2h4M142 26.1v2.1M142 29.2v2" fill="none" stroke="#00f" stroke-width=".25"/>
<path d="M139.5 36.3h5.1M140.2 37h3.6M141 37.8h2M141.8 38.6h.5M142 33.7v2.6M218.3 36.3h5M219 37h3.6M219.8 37.8h2M220.6 38.6h.5M220.8 33.7v2.6" fill="none" stroke="#800000" stroke-width=".25"/>
<path d="M139.5 61.7h33v63.5h-33z" fill-rule="evenodd" fill="#ffffb0"/>
<path d="M139.5 61.7h33v63.5h-33z" fill="none" stroke="#800000" stroke-width=".21"/>
<g fill="none" stroke="#000" stroke-width=".25">
<path d="M131.8 74.4h7.7M131.8 79.5h7.7M131.8 69.3h7.7M131.8 64.2h7.7M131.8 66.8h7.7M131.8 71.8h7.7M172.5 74.4h7.6M172.5 79.5h7.6M172.5 69.3h7.6M172.5 64.2h7.6M131.8 94.7h7.7M131.8 89.6h7.7"/>
<path d="M131.8 87.1h7.7M131.8 82h7.7M131.8 99.8h7.7M172.5 89.6h7.6M172.5 82h7.6M172.5 99.8h7.6M172.5 84.5h7.6M172.5 97.2h7.6M172.5 92.2h7.6M131.8 117.5h7.7M131.8 115h7.7M131.8 102.3h7.7"/>
<path d="M131.8 107.4h7.7M131.8 112.5h7.7M172.5 117.5h7.6M172.5 115h7.6M172.5 107.4h7.6M172.5 104.9h7.6M172.5 112.5h7.6M131.8 120.1h7.7M172.5 122.6h7.6"/>
</g>
<path d="M126.8 127.7h5M127.5 128.5h3.6M128.3 129.2h2M129.1 130h.5M129.3 125.2v2.5M180.1 135.3h5.1M180.9 136.1h3.6M181.7 136.8h2M182.4 137.6h.5M182.7 132.8v2.5" fill="none" stroke="#800000" stroke-width=".25"/>
<path d="M53.1 123.9h13.9l1.3 1.3-1.3 1.2h-13.9z" fill-rule="evenodd" fill="#ffff80"/>
<path d="M53.1 123.9h13.9l1.3 1.3-1.3 1.2h-13.9z" fill="none" stroke="#800000" stroke-width=".21"/>
<path d="M53.1 126.4h13.9l1.3 1.3-1.3 1.3h-13.9z" fill-rule="evenodd" fill="#ffff80"/>
<path d="M53.1 126.4h13.9l1.3 1.3-1.3 1.3h-13.9z" fill="none" stroke="#800000" stroke-width=".21"/>
<g fill="none" stroke="#000" stroke-width=".25">
<path d="M83.6 109.9v2M83.6 118.1v2M236.1 107.4h5M241.1 109.9v2.6M70.8 132.8v2.5M75.9 130.2v2.6"/>
<circle cx="70.8" cy="136.6" r="1.27"/>
<circle cx="75.9" cy="134.1" r="1.27"/>
</g>
<g fill="none" stroke="#00f" stroke-width=".25">
<path d="M82.5 112h2v6h-2z"/>
<circle cx="241.1" cy="107.4" r="2.54"/>
</g>
<path d="M130.8 98.8l2.1 2M130.8 93.7l2.1 2M132.9 98.8l-2.1 2M132.9 93.7l-2.1 2M130.8 101.3l2.1 2M132.9 101.3l-2.1 2" fill="none" stroke="#f00" stroke-width=".21"/>
<circle cx="241.1" cy="107.4" r=".64" fill="#00f"/>
<circle cx="241.1" cy="107.4" r=".64" fill="none" stroke="#00f" stroke-width=".21"/>
<g fill="none" stroke="#800000" stroke-width=".25">
<path d="M269.1 23.6h2.5M271.6 22.3v2.6M115.3 59.1h2.6M116.6 59.1v2.6M128 59.1h2.6M129.3 59.1v2.6M181.4 59.1h2.6M182.7 59.1v2.6M258.9 46.4h2.6M261.5 45.2v2.5M109 79.5v5M189 61.7h2.6"/>
<path d="M190.3 61.7v2.5M106.7 81.7v.5M107.4 81v2M108.2 80.2v3.6M109 82h2.5M238.6 115h5.1M239.4 115.8h3.5M240.1 116.5h2.1M240.9 117.3h.5M241.1 112.5v2.5M187.8 135.3h15.2M188.5 136.1h3.6"/>
<path d="M189.3 136.8h2M190.1 137.6h.5M190.3 132.8v2.5M193.6 136.1h3.6M194.4 136.8h2M195.1 137.6h.5M195.4 132.8v2.5M198.7 136.1h3.5M199.5 136.8h2M200.2 137.6h.5M200.5 132.8v2.5"/>
</g>
<path d="M179.1 98.8l2.1 2M179.1 96.2l2.1 2M181.2 98.8l-2.1 2M181.2 96.2l-2.1 2M179.1 103.8l2.1 2.1M181.2 103.8l-2.1 2.1" fill="none" stroke="#f00" stroke-width=".21"/>
<g fill="none" stroke="#000" stroke-width=".25">
<path d="M233.5 23.6h4.5M239.2 23.6h4.5M233.5 46.4h4.5M239.2 46.4h4.5M111.5 79.5h2.6M119.1 79.5h2.6M119.1 82h2.6M126.8 82h2.5M190.3 107.4h2M198.5 107.4h2M190.3 120.1v2M190.3 128.2v2"/>
<path d="M195.4 120.1v2M195.4 128.2v2M200.5 120.1v2M200.5 128.2v2"/>
</g>
<g fill="none" stroke="#00f" stroke-width=".25">
<path d="M238.6 22.3h1.3l-1.3 2.6h-1.3zM238.6 45.2h1.3l-1.3 2.5h-1.3zM114.1 79.5h2M116.1 77.4v4M117.1 79.5h2M117.1 77.4v4M123.7 80v4M124.7 80v4M121.7 82h2M124.7 82h2.1M192.4 106.4h6v2h-6zM189.3 122.2h2.1v6h-2.1z"/>
<path d="M194.4 122.2h2v6h-2zM199.5 122.2h2v6h-2z"/>
</g>
<circle cx="220.8" cy="23.6" r=".51" fill="#000080"/>
<circle cx="220.8" cy="23.6" r=".51" fill="none" stroke="#000080" stroke-width=".21"/>
<path d="M220.8 23.6v2.5M220.8 31.2v2.5" fill="none" stroke="#000" stroke-width=".25"/>
<circle cx="220.8" cy="23.6" r=".51" fill="#000080"/>
<circle cx="220.8" cy="23.6" r=".51" fill="none" stroke="#000080" stroke-width=".21"/>
<path d="M218.8 29.2h4M218.8 28.2h4M220.8 26.1v2.1M220.8 29.2v2" fill="none" stroke="#00f" stroke-width=".25"/>
<circle cx="253.8" cy="23.6" r=".51" fill="#000080"/>
<circle cx="253.8" cy="23.6" r=".51" fill="none" stroke="#000080" stroke-width=".21"/>
<path d="M253.8 23.6v2.5" fill="none" stroke="#000" stroke-width=".25"/>
<circle cx="253.8" cy="23.6" r=".51" fill="#000080"/>
<circle cx="253.8" cy="23.6" r=".51" fill="none" stroke="#000080" stroke-width=".21"/>
<path d="M253.8 31.2v2.5" fill="none" stroke="#000" stroke-width=".25"/>
<path d="M251.8 28.2h4M251.8 29.2h4M253.8 26.1v2.1M253.8 29.2v2" fill="none" stroke="#00f" stroke-width=".25"/>
<path d="M251.3 36.3h5.1M252.1 37h3.5M252.8 37.8h2.1M253.6 38.6h.5M253.8 33.7v2.6" fill="none" stroke="#800000" stroke-width=".25"/>
<circle cx="253.8" cy="46.4" r=".51" fill="#000080"/>
<circle cx="253.8" cy="46.4" r=".51" fill="none" stroke="#000080" stroke-width=".21"/>
<path d="M253.8 46.4v2.6" fill="none" stroke="#000" stroke-width=".25"/>
<circle cx="253.8" cy="46.4" r=".51" fill="#000080"/>
<circle cx="253.8" cy="46.4" r=".51" fill="none" stroke="#000080" stroke-width=".21"/>
<path d="M253.8 54.1v2.5" fill="none" stroke="#000" stroke-width=".25"/>
<path d="M251.8 51h4M251.8 52h4M253.8 49v2M253.8 52v2.1" fill="none" stroke="#00f" stroke-width=".25"/>
<path d="M26.4 21h2.5M27.6 21v2.6M251.3 59.1h5.1M252.1 59.9h3.5M253.8 56.6v2.5M252.8 60.7h2.1M253.6 61.4h.5" fill="none" stroke="#800000" stroke-width=".25"/>
<circle cx="32.7" cy="23.6" r=".51" fill="#000080"/>
<circle cx="32.7" cy="23.6" r=".51" fill="none" stroke="#000080" stroke-width=".21"/>
<circle cx="32.7" cy="33.7" r=".51" fill="#000080"/>
<circle cx="32.7" cy="33.7" r=".51" fill="none" stroke="#000080" stroke-width=".21"/>
<path d="M32.7 23.6v2.5" fill="none" stroke="#000" stroke-width=".25"/>
<circle cx="32.7" cy="23.6" r=".51" fill="#000080"/>
<circle cx="32.7" cy="23.6" r=".51" fill="none" stroke="#000080" stroke-width=".21"/>
<path d="M32.7 31.2v2.5" fill="none" stroke="#000" stroke-width=".25"/>
<circle cx="32.7" cy="33.7" r=".51" fill="#000080"/>
<circle cx="32.7" cy="33.7" r=".51" fill="none" stroke="#000080" stroke-width=".21"/>
<path d="M30.7 28.2h4M30.7 29.2h4M32.7 26.1v2.1M32.7 29.2v2" fill="none" stroke="#00f" stroke-width=".25"/>
<circle cx="42.9" cy="23.6" r=".51" fill="#000080"/>
<circle cx="42.9" cy="23.6" r=".51" fill="none" stroke="#000080" stroke-width=".21"/>
<circle cx="42.9" cy="33.7" r=".51" fill="#000080"/>
<circle cx="42.9" cy="33.7" r=".51" fill="none" stroke="#000080" stroke-width=".21"/>
<path d="M42.9 23.6v2.5" fill="none" stroke="#000" stroke-width=".25"/>
<circle cx="42.9" cy="23.6" r=".51" fill="#000080"/>
<circle cx="42.9" cy="23.6" r=".51" fill="none" stroke="#000080" stroke-width=".21"/>
<path d="M42.9 31.2v2.5" fill="none" stroke="#000" stroke-width=".25"/>
<circle cx="42.9" cy="33.7" r=".51" fill="#000080"/>
<circle cx="42.9" cy="33.7" r=".51" fill="none" stroke="#000080" stroke-width=".21"/>
<path d="M40.9 28.2h4M40.9 29.2h4M42.9 26.1v2.1M42.9 29.2v2" fill="none" stroke="#00f" stroke-width=".25"/>
<circle cx="53.1" cy="23.6" r=".51" fill="#000080"/>
<circle cx="53.1" cy="23.6" r=".51" fill="none" stroke="#000080" stroke-width=".21"/>
<circle cx="53.1" cy="33.7" r=".51" fill="#000080"/>
<circle cx="53.1" cy="33.7" r=".51" fill="none" stroke="#000080" stroke-width=".21"/>
<path d="M53.1 23.6v2.5" fill="none" stroke="#000" stroke-width=".25"/>
<circle cx="53.1" cy="23.6" r=".51" fill="#000080"/>
<circle cx="53.1" cy="23.6" r=".51" fill="none" stroke="#000080" stroke-width=".21"/>
<path d="M53.1 31.2v2.5" fill="none" stroke="#000" stroke-width=".25"/>
<circle cx="53.1" cy="33.7" r=".51" fill="#000080"/>
<circle cx="53.1" cy="33.7" r=".51" fill="none" stroke="#000080" stroke-width=".21"/>
<path d="M51.1 28.2h4M51.1 29.2h4M53.1 26.1v2.1M53.1 29.2v2" fill="none" stroke="#00f" stroke-width=".25"/>
<circle cx="63.2" cy="23.6" r=".51" fill="#000080"/>
<circle cx="63.2" cy="23.6" r=".51" fill="none" stroke="#000080" stroke-width=".21"/>
<circle cx="63.2" cy="33.7" r=".51" fill="#000080"/>
<circle cx="63.2" cy="33.7" r=".51" fill="none" stroke="#000080" stroke-width=".21"/>
<path d="M63.2 23.6v2.5" fill="none" stroke="#000" stroke-width=".25"/>
<circle cx="63.2" cy="23.6" r=".51" fill="#000080"/>
<circle cx="63.2" cy="23.6" r=".51" fill="none" stroke="#000080" stroke-width=".21"/>
<path d="M63.2 31.2v2.5" fill="none" stroke="#000" stroke-width=".25"/>
<circle cx="63.2" cy="33.7" r=".51" fill="#000080"/>
<circle cx="63.2" cy="33.7" r=".51" fill="none" stroke="#000080" stroke-width=".21"/>
<path d="M61.2 28.2h4M61.2 29.2h4M63.2 26.1v2.1M63.2 29.2v2M117.1 28.2h4M117.1 29.2h4M119.1 26.1v2.1M119.1 29.2v2" fill="none" stroke="#00f" stroke-width=".25"/>
<g fill="none" stroke="#800000" stroke-width=".25">
<path d="M25.1 36.3h5.1M25.9 37h3.5M26.6 37.8h2.1M27.4 38.6h.5M27.6 33.7v2.6M116.6 36.3h5.1M117.4 37h3.5M117.9 21h2.5M118.1 37.8h2.1M118.9 38.6h.5M119.1 21v2.6M119.1 33.7v2.6"/>
<path d="M196.7 64.2h2.5M197.9 64.2v2.6"/>
</g>
<path d="M119.1 23.6v2.5M119.1 31.2v2.5" fill="none" stroke="#000" stroke-width=".25"/>
<circle cx="83.6" cy="23.6" r=".51" fill="#000080"/>
<circle cx="83.6" cy="23.6" r=".51" fill="none" stroke="#000080" stroke-width=".21"/>
<circle cx="83.6" cy="33.7" r=".51" fill="#000080"/>
<circle cx="83.6" cy="33.7" r=".51" fill="none" stroke="#000080" stroke-width=".21"/>
<path d="M83.6 23.6v2.5" fill="none" stroke="#000" stroke-width=".25"/>
<circle cx="83.6" cy="23.6" r=".51" fill="#000080"/>
<circle cx="83.6" cy="23.6" r=".51" fill="none" stroke="#000080" stroke-width=".21"/>
<path d="M83.6 31.2v2.5" fill="none" stroke="#000" stroke-width=".25"/>
<circle cx="83.6" cy="33.7" r=".51" fill="#000080"/>
<circle cx="83.6" cy="33.7" r=".51" fill="none" stroke="#000080" stroke-width=".21"/>
<path d="M81.6 28.2h4M81.6 29.2h4M83.6 26.1v2.1M83.6 29.2v2" fill="none" stroke="#00f" stroke-width=".25"/>
<circle cx="93.7" cy="23.6" r=".51" fill="#000080"/>
<circle cx="93.7" cy="23.6" r=".51" fill="none" stroke="#000080" stroke-width=".21"/>
<circle cx="93.7" cy="33.7" r=".51" fill="#000080"/>
<circle cx="93.7" cy="33.7" r=".51" fill="none" stroke="#000080" stroke-width=".21"/>
<path d="M93.7 23.6v2.5" fill="none" stroke="#000" stroke-width=".25"/>
<circle cx="93.7" cy="23.6" r=".51" fill="#000080"/>
<circle cx="93.7" cy="23.6" r=".51" fill="none" stroke="#000080" stroke-width=".21"/>
<path d="M93.7 31.2v2.5" fill="none" stroke="#000" stroke-width=".25"/>
<circle cx="93.7" cy="33.7" r=".51" fill="#000080"/>
<circle cx="93.7" cy="33.7" r=".51" fill="none" stroke="#000080" stroke-width=".21"/>
<path d="M91.7 28.2h4M91.7 29.2h4M93.7 26.1v2.1M93.7 29.2v2" fill="none" stroke="#00f" stroke-width=".25"/>
<circle cx="73.4" cy="23.6" r=".51" fill="#000080"/>
<circle cx="73.4" cy="23.6" r=".51" fill="none" stroke="#000080" stroke-width=".21"/>
<circle cx="73.4" cy="33.7" r=".51" fill="#000080"/>
<circle cx="73.4" cy="33.7" r=".51" fill="none" stroke="#000080" stroke-width=".21"/>
<path d="M73.4 23.6v2.5" fill="none" stroke="#000" stroke-width=".25"/>
<circle cx="73.4" cy="23.6" r=".51" fill="#000080"/>
<circle cx="73.4" cy="23.6" r=".51" fill="none" stroke="#000080" stroke-width=".21"/>
<path d="M73.4 31.2v2.5" fill="none" stroke="#000" stroke-width=".25"/>
<circle cx="73.4" cy="33.7" r=".51" fill="#000080"/>
<circle cx="73.4" cy="33.7" r=".51" fill="none" stroke="#000080" stroke-width=".21"/>
<path d="M71.4 28.2h4M71.4 29.2h4M73.4 26.1v2.1M73.4 29.2v2" fill="none" stroke="#00f" stroke-width=".25"/>
<circle cx="264" cy="23.6" r=".51" fill="#000080"/>
<circle cx="264" cy="23.6" r=".51" fill="none" stroke="#000080" stroke-width=".21"/>
<path d="M264 23.6v2.5" fill="none" stroke="#000" stroke-width=".25"/>
<circle cx="264" cy="23.6" r=".51" fill="#000080"/>
<circle cx="264" cy="23.6" r=".51" fill="none" stroke="#000080" stroke-width=".21"/>
<path d="M264 31.2v2.5" fill="none" stroke="#000" stroke-width=".25"/>
<path d="M262 28.2h4M262 29.2h4M264 26.1v2.1M264 29.2v2" fill="none" stroke="#00f" stroke-width=".25"/>
<path d="M261.5 36.3h5.1M262.2 37h3.6M263 37.8h2M263.8 38.6h.5M264 33.7v2.6" fill="none" stroke="#800000" stroke-width=".25"/>
<path d="M53.1 84.5h20.3v15.3h-20.3z" fill-rule="evenodd" fill="#ffffb0"/>
<path d="M53.1 84.5h20.3v15.3h-20.3z" fill="none" stroke="#800000" stroke-width=".21"/>
<path d="M45.4 87.1h7.7M45.4 97.2h7.7M45.4 92.1h7.7M73.4 87.1h7.6M111.5 87.1h2.6M119.1 87.1h2.6M119.1 89.6h2.6M126.8 89.6h2.5" fill="none" stroke="#000" stroke-width=".25"/>
<path d="M41.6 82h2.6M42.9 82v2.5M42.9 99.8v2.5M106.7 89.4v.5M107.4 88.6v2M108.2 87.8v3.6M109 87.1v5M109 89.6h2.5M40.3 102.3h5.1M41.1 103.1h3.6M41.9 103.8h2M42.6 104.6h.5" fill="none" stroke="#800000" stroke-width=".25"/>
<path d="M114.1 87.1h2M116.1 85.1v4M117.1 87.1h2M117.1 85.1v4M121.7 89.6h2M123.7 87.6v4M124.7 89.6h2.1M124.7 87.6v4" fill="none" stroke="#00f" stroke-width=".25"/>
<path d="M152.2 29.9h14l1.2 1.3-1.2 1.3h-14z" fill-rule="evenodd" fill="#ffff80"/>
<path d="M152.2 29.9h14l1.2 1.3-1.2 1.3h-14z" fill="none" stroke="#800000" stroke-width=".21"/>
<path d="M103.9 23.6v2.5M103.9 31.2v2.5" fill="none" stroke="#000" stroke-width=".25"/>
<path d="M101.9 28.2h4M101.9 29.2h4M103.9 26.1v2.1M103.9 29.2v2" fill="none" stroke="#00f" stroke-width=".25"/>
<path d="M205.6 90.9h16.5l1.2 1.3-1.2 1.2h-16.5z" fill-rule="evenodd" fill="#ffff80"/>
<path d="M205.6 90.9h16.5l1.2 1.3-1.2 1.2h-16.5z" fill="none" stroke="#800000" stroke-width=".21"/>
<path d="M205.6 88.3h16.5l1.2 1.3-1.2 1.3h-16.5z" fill-rule="evenodd" fill="#ffff80"/>
<path d="M205.6 88.3h16.5l1.2 1.3-1.2 1.3h-16.5z" fill="none" stroke="#800000" stroke-width=".21"/>
<circle cx="220.8" cy="107.4" r=".51" fill="#000080"/>
<circle cx="220.8" cy="107.4" r=".51" fill="none" stroke="#000080" stroke-width=".21"/>
<path d="M220.8 107.4v4.4M220.8 118.2v4.4" fill="none" stroke="#000" stroke-width=".25"/>
<circle cx="220.8" cy="107.4" r=".51" fill="#000080"/>
<circle cx="220.8" cy="107.4" r=".51" fill="none" stroke="#000080" stroke-width=".21"/>
<path d="M220.8 115l1.9 3.2h-3.8z" fill="#00f"/>
<path d="M219.5 115h2.6M220.8 115l1.9 3.2h-3.8z" fill="none" stroke="#00f" stroke-width=".25"/>
<path d="M218.9 111.8h3.8l-1.9 3.2z" fill="#00f"/>
<path d="M218.9 111.8h3.8l-1.9 3.2zM219.5 115l-1.2 1.3M223.3 113.7l-1.2 1.3" fill="none" stroke="#00f" stroke-width=".25"/>
<path d="M91.2 107.4h-2.6v2.5" fill="none" stroke="#000080" stroke-width=".25"/>
<circle cx="88.6" cy="107.4" r=".51" fill="#000080"/>
<circle cx="88.6" cy="107.4" r=".51" fill="none" stroke="#000080" stroke-width=".21"/>
<circle cx="91.2" cy="107.4" r=".51" fill="#000080"/>
<circle cx="91.2" cy="107.4" r=".51" fill="none" stroke="#000080" stroke-width=".21"/>
<path d="M91.2 104.8v2.6h2.5v2.5" fill="none" stroke="#000080" stroke-width=".25"/>
<circle cx="91.2" cy="107.4" r=".51" fill="#000080"/>
<circle cx="91.2" cy="107.4" r=".51" fill="none" stroke="#000080" stroke-width=".21"/>
<path d="M88.6 120.1v5.1" fill="none" stroke="#000080" stroke-width=".25"/>
<circle cx="88.6" cy="125.2" r=".51" fill="#000080"/>
<circle cx="88.6" cy="125.2" r=".51" fill="none" stroke="#000080" stroke-width=".21"/>
<path d="M175.1 23.6v2.5h2.5" fill="none" stroke="#000080" stroke-width=".25"/>
<circle cx="175.1" cy="23.6" r=".51" fill="#000080"/>
<circle cx="175.1" cy="23.6" r=".51" fill="none" stroke="#000080" stroke-width=".21"/>
<path d="M210.6 23.6v2.5h-2.5" fill="none" stroke="#000080" stroke-width=".25"/>
<circle cx="210.6" cy="23.6" r=".51" fill="#000080"/>
<circle cx="210.6" cy="23.6" r=".51" fill="none" stroke="#000080" stroke-width=".21"/>
<path d="M167.4 31.2h10.2M208.1 31.2h2.5v2.5M180.1 89.6h25.5M180.1 92.2h25.5M131.8 117.5h-2.5v7.7" fill="none" stroke="#000080" stroke-width=".25"/>
<circle cx="129.3" cy="120.1" r=".51" fill="#000080"/>
<circle cx="129.3" cy="120.1" r=".51" fill="none" stroke="#000080" stroke-width=".21"/>
<path d="M129.3 120.1h2.5" fill="none" stroke="#000080" stroke-width=".25"/>
<circle cx="129.3" cy="120.1" r=".51" fill="#000080"/>
<circle cx="129.3" cy="120.1" r=".51" fill="none" stroke="#000080" stroke-width=".21"/>
<path d="M75.9 125.2v5" fill="none" stroke="#000080" stroke-width=".25"/>
<circle cx="75.9" cy="125.2" r=".51" fill="#000080"/>
<circle cx="75.9" cy="125.2" r=".51" fill="none" stroke="#000080" stroke-width=".21"/>
<path d="M93.7 120.1v7.6" fill="none" stroke="#000080" stroke-width=".25"/>
<circle cx="93.7" cy="127.7" r=".51" fill="#000080"/>
<circle cx="93.7" cy="127.7" r=".51" fill="none" stroke="#000080" stroke-width=".21"/>
<path d="M88.6 107.4h-5v2.5" fill="none" stroke="#000080" stroke-width=".25"/>
<circle cx="88.6" cy="107.4" r=".51" fill="#000080"/>
<circle cx="88.6" cy="107.4" r=".51" fill="none" stroke="#000080" stroke-width=".21"/>
<path d="M83.6 120.1v2.5" fill="none" stroke="#000080" stroke-width=".25"/>
<circle cx="83.6" cy="122.6" r=".51" fill="#000080"/>
<circle cx="83.6" cy="122.6" r=".51" fill="none" stroke="#000080" stroke-width=".21"/>
<path d="M70.8 122.6v10.2" fill="none" stroke="#000080" stroke-width=".25"/>
<circle cx="70.8" cy="122.6" r=".51" fill="#000080"/>
<circle cx="70.8" cy="122.6" r=".51" fill="none" stroke="#000080" stroke-width=".21"/>
<path d="M131.8 115h-25.4v12.7h-38.1" fill="none" stroke="#000080" stroke-width=".25"/>
<circle cx="81" cy="127.7" r=".51" fill="#000080"/>
<circle cx="81" cy="127.7" r=".51" fill="none" stroke="#000080" stroke-width=".21"/>
<circle cx="93.7" cy="127.7" r=".51" fill="#000080"/>
<circle cx="93.7" cy="127.7" r=".51" fill="none" stroke="#000080" stroke-width=".21"/>
<path d="M131.8 112.5h-27.9v12.7h-35.6" fill="none" stroke="#000080" stroke-width=".25"/>
<circle cx="75.9" cy="125.2" r=".51" fill="#000080"/>
<circle cx="75.9" cy="125.2" r=".51" fill="none" stroke="#000080" stroke-width=".21"/>
<circle cx="88.6" cy="125.2" r=".51" fill="#000080"/>
<circle cx="88.6" cy="125.2" r=".51" fill="none" stroke="#000080" stroke-width=".21"/>
<path d="M131.8 107.4h-30.5v15.2h-33" fill="none" stroke="#000080" stroke-width=".25"/>
<circle cx="70.8" cy="122.6" r=".51" fill="#000080"/>
<circle cx="70.8" cy="122.6" r=".51" fill="none" stroke="#000080" stroke-width=".21"/>
<circle cx="83.6" cy="122.6" r=".51" fill="#000080"/>
<circle cx="83.6" cy="122.6" r=".51" fill="none" stroke="#000080" stroke-width=".21"/>
<g fill="none" stroke="#000080" stroke-width=".25">
<path d="M96.3 79.5h15.2M121.7 79.5h10.1M129.3 61.7v10.1h2.5M111.5 82h7.6M129.3 82h2.5M180.1 117.5h10.2v2.6M180.1 115h15.3v5.1M180.1 112.5h20.4v7.6M180.1 107.4h10.2M180.1 122.6h2.6v10.2M190.3 130.2v2.6M195.4 130.2v2.6"/>
<path d="M200.5 130.2v2.6"/>
</g>
<circle cx="129.3" cy="69.3" r=".51" fill="#000080"/>
<circle cx="129.3" cy="69.3" r=".51" fill="none" stroke="#000080" stroke-width=".21"/>
<circle cx="129.3" cy="66.8" r=".51" fill="#000080"/>
<circle cx="129.3" cy="66.8" r=".51" fill="none" stroke="#000080" stroke-width=".21"/>
<circle cx="129.3" cy="64.2" r=".51" fill="#000080"/>
<circle cx="129.3" cy="64.2" r=".51" fill="none" stroke="#000080" stroke-width=".21"/>
<path d="M129.3 69.3h2.5" fill="none" stroke="#000080" stroke-width=".25"/>
<circle cx="129.3" cy="69.3" r=".51" fill="#000080"/>
<circle cx="129.3" cy="69.3" r=".51" fill="none" stroke="#000080" stroke-width=".21"/>
<path d="M129.3 66.8h2.5" fill="none" stroke="#000080" stroke-width=".25"/>
<circle cx="129.3" cy="66.8" r=".51" fill="#000080"/>
<circle cx="129.3" cy="66.8" r=".51" fill="none" stroke="#000080" stroke-width=".21"/>
<path d="M129.3 64.2h2.5" fill="none" stroke="#000080" stroke-width=".25"/>
<circle cx="129.3" cy="64.2" r=".51" fill="#000080"/>
<circle cx="129.3" cy="64.2" r=".51" fill="none" stroke="#000080" stroke-width=".21"/>
<path d="M208.1 23.6h25.4M116.6 61.7v12.7h15.2" fill="none" stroke="#000080" stroke-width=".25"/>
<circle cx="210.6" cy="23.6" r=".51" fill="#000080"/>
<circle cx="210.6" cy="23.6" r=".51" fill="none" stroke="#000080" stroke-width=".21"/>
<circle cx="220.8" cy="23.6" r=".51" fill="#000080"/>
<circle cx="220.8" cy="23.6" r=".51" fill="none" stroke="#000080" stroke-width=".21"/>
<circle cx="231" cy="23.6" r=".51" fill="#000080"/>
<circle cx="231" cy="23.6" r=".51" fill="none" stroke="#000080" stroke-width=".21"/>
<path d="M231 23.6v22.8h2.5" fill="none" stroke="#000080" stroke-width=".25"/>
<circle cx="231" cy="23.6" r=".51" fill="#000080"/>
<circle cx="231" cy="23.6" r=".51" fill="none" stroke="#000080" stroke-width=".21"/>
<path d="M243.7 23.6h25.4" fill="none" stroke="#000080" stroke-width=".25"/>
<circle cx="253.8" cy="23.6" r=".51" fill="#000080"/>
<circle cx="253.8" cy="23.6" r=".51" fill="none" stroke="#000080" stroke-width=".21"/>
<circle cx="264" cy="23.6" r=".51" fill="#000080"/>
<circle cx="264" cy="23.6" r=".51" fill="none" stroke="#000080" stroke-width=".21"/>
<path d="M243.7 46.4h15.2" fill="none" stroke="#000080" stroke-width=".25"/>
<circle cx="253.8" cy="46.4" r=".51" fill="#000080"/>
<circle cx="253.8" cy="46.4" r=".51" fill="none" stroke="#000080" stroke-width=".21"/>
<path d="M182.7 64.2v5.1h-2.6" fill="none" stroke="#000080" stroke-width=".25"/>
<circle cx="182.7" cy="64.2" r=".51" fill="#000080"/>
<circle cx="182.7" cy="64.2" r=".51" fill="none" stroke="#000080" stroke-width=".21"/>
<path d="M182.7 79.5v2.5h-2.6M190.3 64.2v10.2h-10.2" fill="none" stroke="#000080" stroke-width=".25"/>
<circle cx="182.7" cy="82" r=".51" fill="#000080"/>
<circle cx="182.7" cy="82" r=".51" fill="none" stroke="#000080" stroke-width=".21"/>
<circle cx="182.7" cy="79.5" r=".51" fill="#000080"/>
<circle cx="182.7" cy="79.5" r=".51" fill="none" stroke="#000080" stroke-width=".21"/>
<path d="M182.7 82v2.5h-2.6" fill="none" stroke="#000080" stroke-width=".25"/>
<circle cx="182.7" cy="82" r=".51" fill="#000080"/>
<circle cx="182.7" cy="82" r=".51" fill="none" stroke="#000080" stroke-width=".21"/>
<path d="M182.7 61.7v2.5h-2.6" fill="none" stroke="#000080" stroke-width=".25"/>
<circle cx="182.7" cy="64.2" r=".51" fill="#000080"/>
<circle cx="182.7" cy="64.2" r=".51" fill="none" stroke="#000080" stroke-width=".21"/>
<path d="M42.9 84.5v2.6h2.5" fill="none" stroke="#000080" stroke-width=".25"/>
<circle cx="42.9" cy="87.1" r=".51" fill="#000080"/>
<circle cx="42.9" cy="87.1" r=".51" fill="none" stroke="#000080" stroke-width=".21"/>
<path d="M136.9 21v2.6h40.7M45.4 97.2h-2.5v2.6M81 87.1h30.5M111.5 89.6h7.6M121.7 87.1h10.1M129.3 89.6h2.5" fill="none" stroke="#000080" stroke-width=".25"/>
<circle cx="142" cy="23.6" r=".51" fill="#000080"/>
<circle cx="142" cy="23.6" r=".51" fill="none" stroke="#000080" stroke-width=".21"/>
<circle cx="175.1" cy="23.6" r=".51" fill="#000080"/>
<circle cx="175.1" cy="23.6" r=".51" fill="none" stroke="#000080" stroke-width=".21"/>
<path d="M197.9 66.8v12.7h-17.8" fill="none" stroke="#000080" stroke-width=".25"/>
<circle cx="182.7" cy="79.5" r=".51" fill="#000080"/>
<circle cx="182.7" cy="79.5" r=".51" fill="none" stroke="#000080" stroke-width=".21"/>
<path d="M27.6 23.6h76.3" fill="none" stroke="#000080" stroke-width=".25"/>
<circle cx="32.7" cy="23.6" r=".51" fill="#000080"/>
<circle cx="32.7" cy="23.6" r=".51" fill="none" stroke="#000080" stroke-width=".21"/>
<circle cx="42.9" cy="23.6" r=".51" fill="#000080"/>
<circle cx="42.9" cy="23.6" r=".51" fill="none" stroke="#000080" stroke-width=".21"/>
<circle cx="53.1" cy="23.6" r=".51" fill="#000080"/>
<circle cx="53.1" cy="23.6" r=".51" fill="none" stroke="#000080" stroke-width=".21"/>
<circle cx="63.2" cy="23.6" r=".51" fill="#000080"/>
<circle cx="63.2" cy="23.6" r=".51" fill="none" stroke="#000080" stroke-width=".21"/>
<circle cx="73.4" cy="23.6" r=".51" fill="#000080"/>
<circle cx="73.4" cy="23.6" r=".51" fill="none" stroke="#000080" stroke-width=".21"/>
<circle cx="83.6" cy="23.6" r=".51" fill="#000080"/>
<circle cx="83.6" cy="23.6" r=".51" fill="none" stroke="#000080" stroke-width=".21"/>
<circle cx="93.7" cy="23.6" r=".51" fill="#000080"/>
<circle cx="93.7" cy="23.6" r=".51" fill="none" stroke="#000080" stroke-width=".21"/>
<path d="M27.6 33.7h76.3" fill="none" stroke="#000080" stroke-width=".25"/>
<circle cx="32.7" cy="33.7" r=".51" fill="#000080"/>
<circle cx="32.7" cy="33.7" r=".51" fill="none" stroke="#000080" stroke-width=".21"/>
<circle cx="42.9" cy="33.7" r=".51" fill="#000080"/>
<circle cx="42.9" cy="33.7" r=".51" fill="none" stroke="#000080" stroke-width=".21"/>
<circle cx="53.1" cy="33.7" r=".51" fill="#000080"/>
<circle cx="53.1" cy="33.7" r=".51" fill="none" stroke="#000080" stroke-width=".21"/>
<circle cx="63.2" cy="33.7" r=".51" fill="#000080"/>
<circle cx="63.2" cy="33.7" r=".51" fill="none" stroke="#000080" stroke-width=".21"/>
<circle cx="73.4" cy="33.7" r=".51" fill="#000080"/>
<circle cx="73.4" cy="33.7" r=".51" fill="none" stroke="#000080" stroke-width=".21"/>
<circle cx="83.6" cy="33.7" r=".51" fill="#000080"/>
<circle cx="83.6" cy="33.7" r=".51" fill="none" stroke="#000080" stroke-width=".21"/>
<circle cx="93.7" cy="33.7" r=".51" fill="#000080"/>
<circle cx="93.7" cy="33.7" r=".51" fill="none" stroke="#000080" stroke-width=".21"/>
<path d="M218.3 125.2h5M219 125.9h3.6M219.8 126.7h2M220.6 127.5h.5M220.8 122.6v2.6" fill="none" stroke="#800000" stroke-width=".25"/>
<path d="M200.5 107.4h35.6" fill="none" stroke="#000080" stroke-width=".25"/>
<circle cx="220.8" cy="107.4" r=".51" fill="#000080"/>
<circle cx="220.8" cy="107.4" r=".51" fill="none" stroke="#000080" stroke-width=".21"/>
<path d="M42.9 87.1v5h2.5" fill="none" stroke="#000080" stroke-width=".25"/>
<circle cx="42.9" cy="87.1" r=".51" fill="#000080"/>
<circle cx="42.9" cy="87.1" r=".51" fill="none" stroke="#000080" stroke-width=".21"/>
<use href="#words"/>
</svg>
